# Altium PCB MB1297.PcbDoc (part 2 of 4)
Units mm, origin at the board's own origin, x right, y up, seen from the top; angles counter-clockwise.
Board outline 90.1 x 62.11 mm, 4 copper layers (Top Layer, GND, POWER+GND, Bottom Layer), stack 0.778 mm thick; 235 components, 174 nets, 1727 pads, 1 vias.

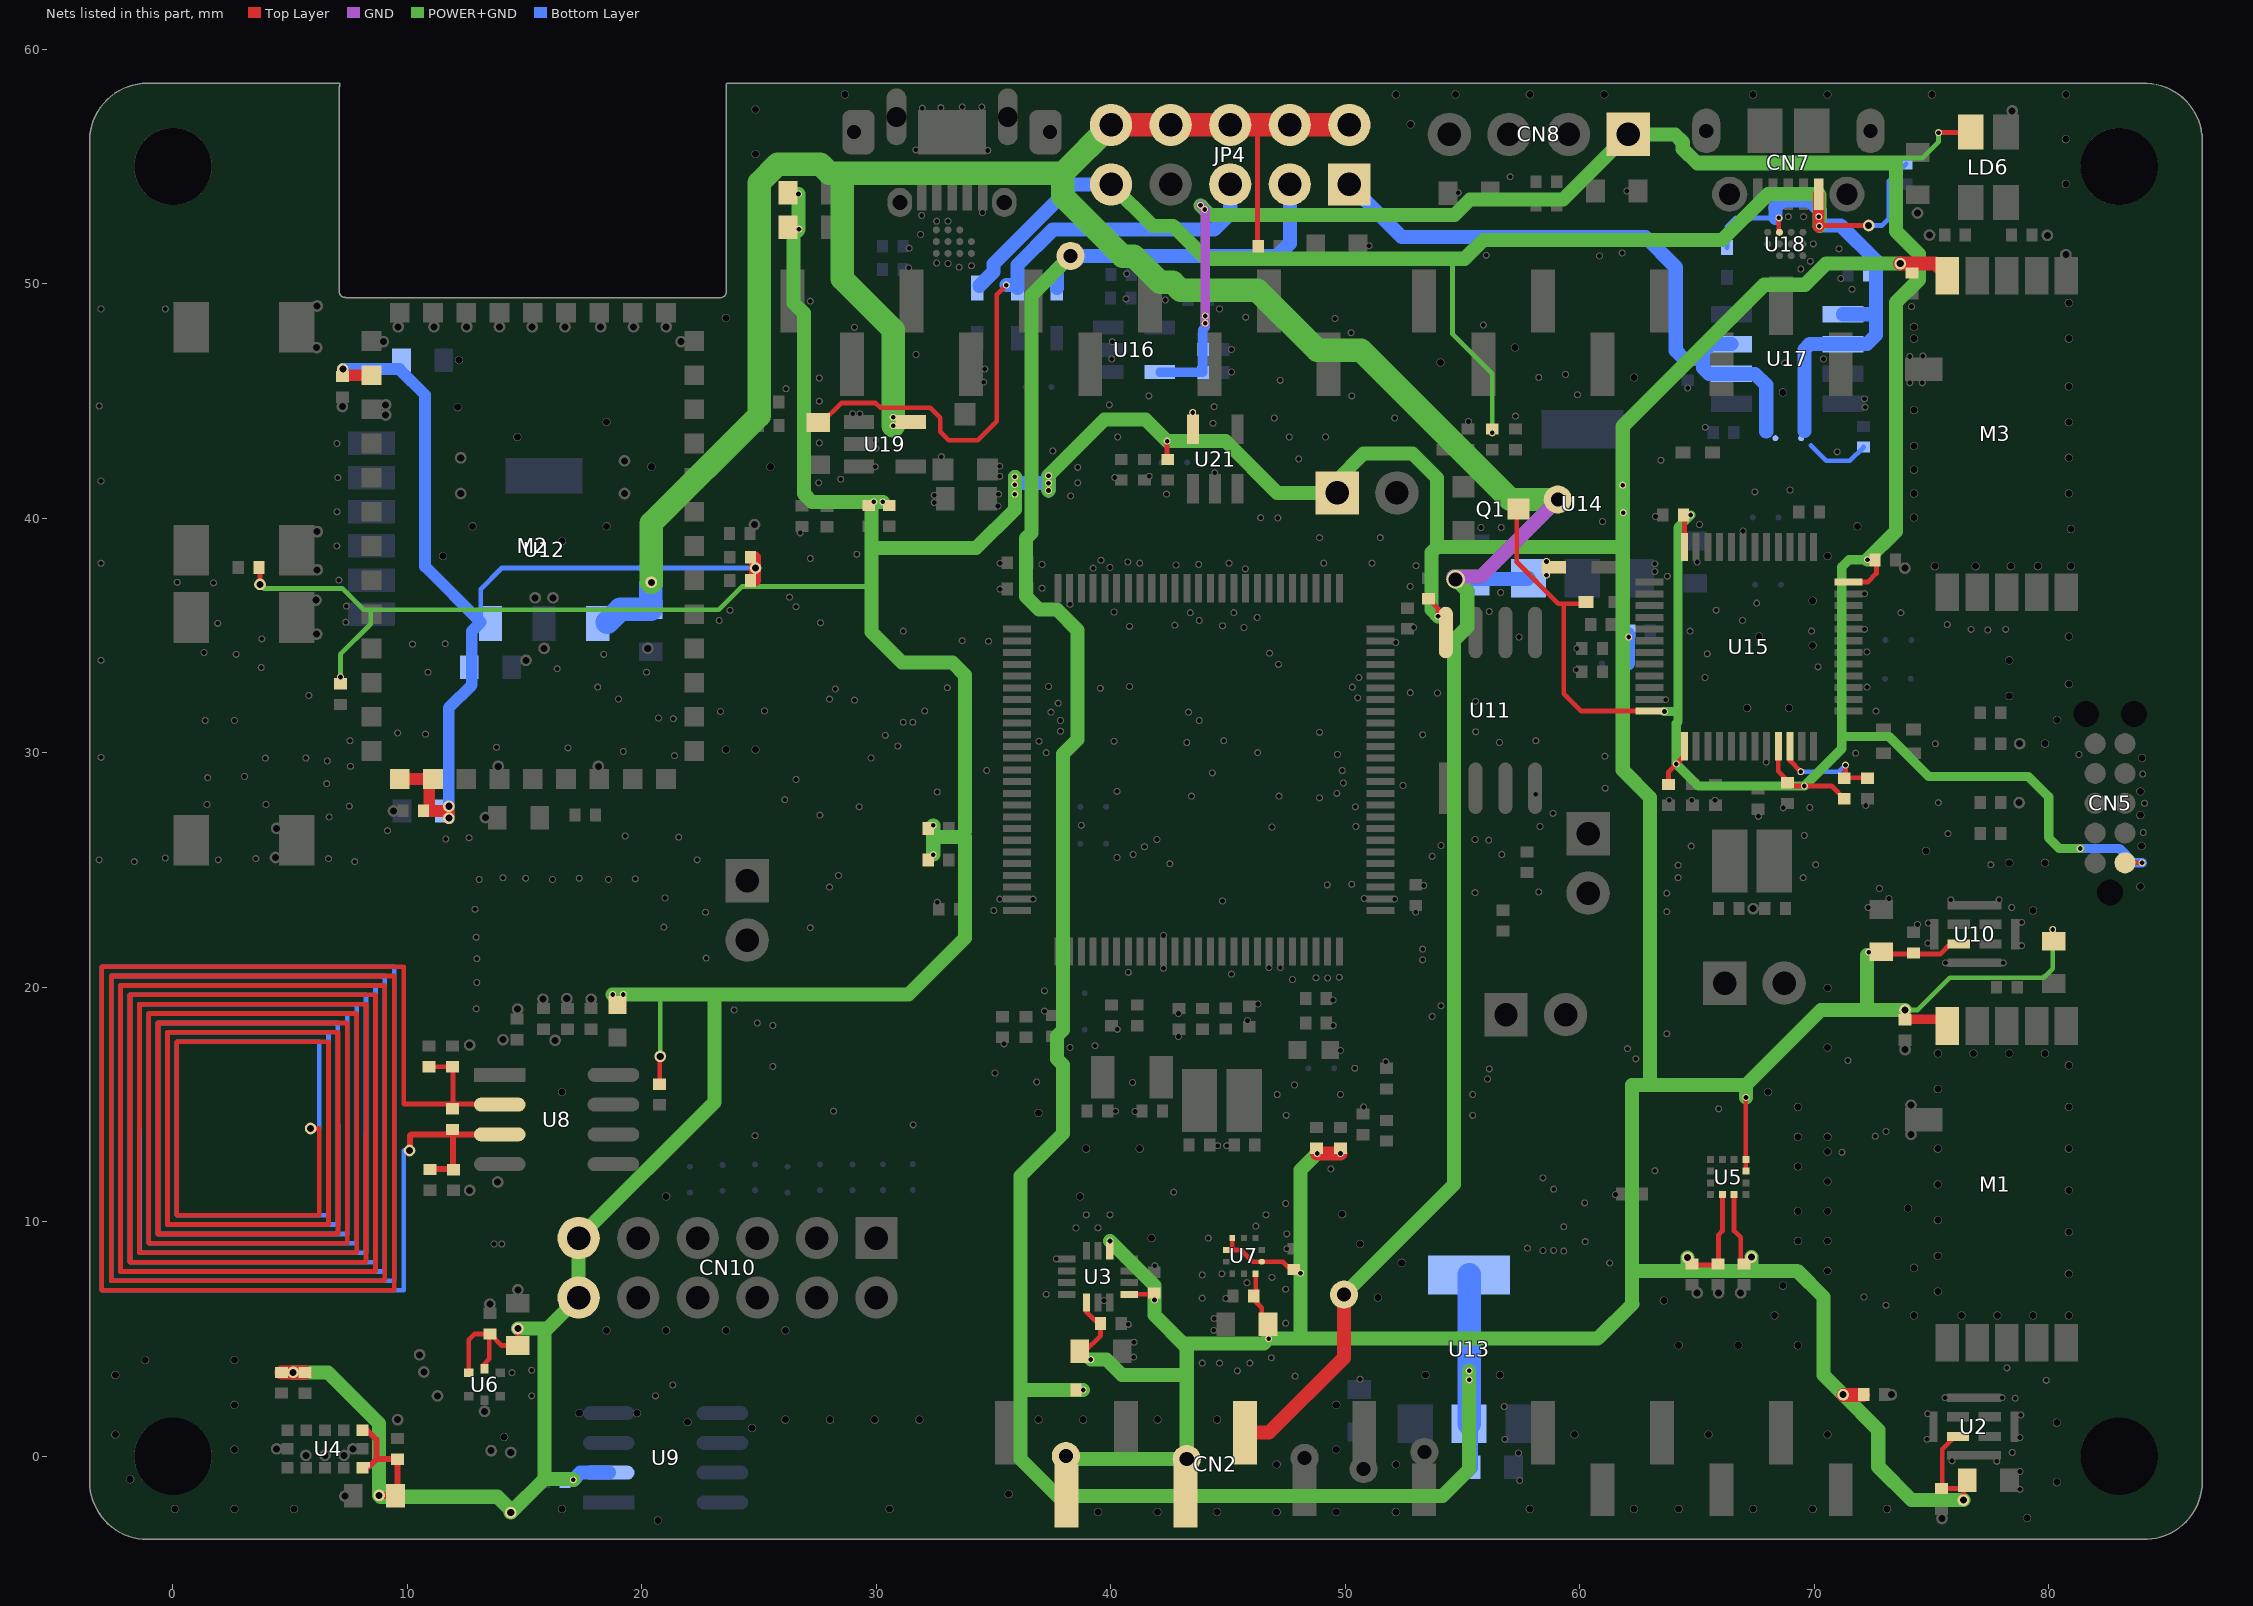
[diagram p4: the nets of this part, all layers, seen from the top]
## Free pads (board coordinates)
  round 0.3 hole 0.2 mask+0.05: 0(-3.068,48.925) 0(17.074,-1.011) 0(24.825,13.666) 0(31.928,52.913) 0(84.003,29.088) 1(-0.325,48.925) 1(6.992,43.187) 1(31.565,14.127) 1(32.568,52.667) 1(84.028,26.599) 2(-3.144,25.43) 2(7.034,41.73) 2(21.316,3.036) 2(28.174,14.711) 2(32.568,50.881) 2(83.978,25.303) 3(-0.325,25.506) 3(6.999,40.273) 3(20.579,2.57) 3(64.115,29.52) 4(-1.646,25.354) 4(6.99,38.816) 4(33.533,50.703) 4(69.576,28.58) 5(-3.068,29.799) 5(7.076,37.359) 5(34.055,50.766) 5(63.658,32.263) 6(-3.068,33.939) 6(7.397,36.251) 6(33.051,52.667) 6(72.141,36.784) 7(-3.068,38.079) 7(7.371,35.565) 7(33.055,50.86) 7(72.141,35.26) 8(-3.068,41.585) 8(31.882,52.1) 8(46.767,34.244) 8(67.95,29.596) 9(-3.144,44.785) 9(39.578,38.206) 9(47.148,33.766) 9(72.268,38.232) 10(1.732,37.241) 10(39.959,37.902) 10(65.004,38.13) 11(0.183,37.267) 11(47.452,10.774) 11(63.225,40.075) 11(68.89,52.862) 12(1.91,35.514) 12(46.614,10.292) 12(64.724,40.137) 12(69.54,52.862) 13(1.478,28.935) 13(39.959,10.292) 13(66.96,39.451) 13(69.423,50.627) 14(3.053,28.986) 14(38.951,10.292) 14(68.964,41.201) 14(69.83,50.957) 15(1.377,31.374) 15(15.296,2.57) 15(59.873,34.447) 15(69.957,51.7) 16(2.621,31.374) 16(15.296,3.662) 16(59.848,33.533) 16(68.488,52.807) 17(1.326,34.269) 17(39.451,9.737) 17(70.19,52.862) 18(2.698,34.193) 18(38.512,9.733) 18(67.464,41.123) 18(70.215,52.456) 19(6.558,28.681) 19(35.54,49.941) 19(47.095,15.423) 19(74.148,49.027) 20(7.524,27.716) 20(29.291,44.455) 20(47.478,14.534) 20(70.973,42.829) 21(1.936,25.43) 21(32.466,40.975) 21(48.799,12.908) 21(76.688,35.26) 22(3.536,25.481) 22(32.466,40.67) 22(49.789,12.908) 22(77.399,35.235) 23(1.453,27.792) 23(37.242,6.9) 23(47.222,45.879) 23(78.161,35.26) 24(3.968,27.792) 24(46.238,35.768) 24(47.605,43.464) 25(6.66,27.259) 25(43.769,35.641) 25(48.011,42.524) 25(72.598,13.645) 26(6.635,25.481) 26(43.388,35.971) 27(7.752,25.354) 27(31.691,46.982) 27(37.445,31.729) 27(73.056,13.848) 28(13.061,24.592) 28(31.374,50.678) 28(37.851,31.374) 28(61.083,28.48) 29(12.934,19.08) 29(31.4,51.516) 29(43.769,31.374) 29(64.191,25.202) 30(12.959,20.198) 30(43.312,31.729) 30(47.744,20.325) 31(12.959,21.214) 31(46.259,30.002) 31(46.868,26.827) 31(77.526,25.227) 32(12.934,22.128) 32(37.242,30.002) 32(40.95,25.659) 32(70.058,25.227) 33(12.883,23.322) 33(18.75,19.69) 33(33.66,34.777) 33(58.298,26.853) 34(14.077,24.668) 34(19.208,19.69) 34(63.708,24.008) 35(15.042,24.643) 35(37.851,30.917) 35(45.395,3.637) 35(69.804,27.665) 36(16.185,24.592) 36(44.76,35.412) 36(46.271,19.283) 36(64.191,24.668) 37(17.328,24.643) 37(44.735,7.777) 37(44.811,30.51) 37(69.525,24.668) 38(18.573,24.592) 38(37.525,42.868) 38(45.801,7.396) 38(69.576,26.472) 39(19.716,24.617) 39(44.158,9.293) 39(64.75,26.014) 40(20.935,22.56) 40(45.674,35.336) 40(58.857,27.411) 41(20.986,23.805) 41(46.182,9.809) 41(63.607,31.755) 42(9.149,26.675) 42(48.087,7.803) 42(63.708,18.013) 43(11.638,26.319) 43(44.9,6.725) 43(47.833,15.829) 43(61.067,29.85) 43(62.032,17.378) 44(12.629,26.37) 44(44.404,5.872) 44(50.399,16.54) 44(62.388,16.947) 45(19.284,26.446) 45(44.392,5.364) 45(50.78,14.889) 45(65.817,36.073) 45(84.079,27.843) 46(21.57,26.395) 46(46.729,5.009) 46(51.725,16.825) 46(63.708,23.22) 46(81.285,29.926) 47(22.357,25.43) 47(37.165,19.842) 47(38.816,2.824) 47(55.53,24.033) 48(22.713,23.195) 48(39.147,4.12) 48(40.747,20.63) 49(22.738,21.239) 49(58.247,24.059) 50(23.932,19.029) 50(38.258,17.429) 50(40.988,4.856) 50(48.9,39.172) 50(67.544,36.378) 51(13.797,30.231) 51(39.324,17.505) 51(40.975,4.221) 51(49.078,38.079) 52(16.845,30.205) 52(40.747,5.618) 52(42.88,18.877) 52(56.114,26.268) 53(19.208,30.053) 53(40.264,25.532) 53(41.864,6.66) 53(56.673,25.659) 53(61.829,41.407) 54(21.392,29.875) 54(38.74,26.903) 54(41.875,8.125) 54(55.53,26.294) 54(61.854,40.238) 55(20.706,31.475) 55(39.705,6.634) 55(40.264,28.351) 55(56.622,36.835) 56(14.458,3.561) 56(21.341,31.45) 56(39.959,9.174) 57(14.026,9.047) 57(23.348,31.755) 57(27.183,22.535) 57(37.673,8.412) 57(55.885,48.239) 58(13.696,9.047) 58(24.923,18.471) 58(25.227,31.78) 58(50.272,45.217) 58(53.929,32.542) 59(20.198,33.431) 59(25.583,18.369) 59(51.008,51.618) 59(53.294,30.764) 59(74.072,46.893) 60(16.388,33.584) 60(25.583,16.616) 60(52.768,32.561) 60(74.63,46.919) 61(18.369,34.193) 61(50.805,23.779) 61(56.571,30.434) 61(74.072,45.776) 62(10.876,33.431) 62(52.101,23.754) 62(55.555,30.891) 62(74.605,45.776) 63(11.613,34.65) 63(42.322,49.306) 63(53,23.2) 63(55.553,32.188) 63(64.6,45.55) 64(10.216,34.625) 64(40.671,50.424) 64(53.345,24.338) 64(58.12,30.51) 64(65.35,43.875) 65(3.942,29.768) 65(40.645,49.357) 65(44.328,29.139) 65(58.12,28.224) 65(72.141,45.09) 66(5.669,29.774) 66(45.141,47.198) 66(47.224,20.833) 66(56.139,36.022) 66(72.167,44.734) 67(5.796,32.441) 67(45.141,46.233) 67(53.955,35.819) 67(68.738,46.614) 68(3.764,33.634) 68(52.913,35.336) 68(59.39,46.131) 69(3.79,34.854) 69(46.741,20.833) 69(52.151,34.701) 69(56.012,51.211) 69(70.389,46.792) 70(6.584,29.647) 70(48.748,20.401) 70(56.8,0.716) 70(60.838,51.186) 70(72.243,34.295) 71(7.574,29.418) 71(49.244,20.389) 71(56.774,2.113) 71(63.734,37.523) 71(72.243,32.796) 72(7.549,30.51) 72(49.744,20.421) 72(57.384,0.132) 72(75.299,56.444) 72(75.697,26.548) 73(9.581,30.84) 73(41.433,25.989) 73(57.435,-1.037) 73(81.336,25.913) 74(10.775,30.79) 74(56.647,39.603) 74(71.049,51.491) 74(75.291,27.869) 75(39.553,32.745) 75(49.561,48.519) 75(55.784,39.603) 75(59.314,9.784) 75(75.164,30.383) 76(37.343,32.822) 76(37.343,41.178) 76(51.135,38.079) 76(59.314,8.742) 76(72.294,23.398) 77(37.343,41.813) 77(57.028,54.564) 77(58.426,8.768) 77(73.183,23.779) 78(37.343,41.496) 78(58.882,8.768) 78(74.4,22.675) 79(35.905,41.762) 79(60.229,9.149) 79(72.319,21.493) 80(35.895,41.432) 80(60.203,10.8) 80(74.859,22.738) 81(35.905,41.026) 81(50.246,47.909) 81(58.426,11.866) 81(74.84,21.874) 82(31.958,57.485) 82(58.882,11.384) 82(75.824,23.728) 83(7.143,33.228) 83(32.746,57.51) 83(41.966,26.295) 83(77.882,23.728) 84(34.498,57.536) 84(42.512,25.266) 84(78.84,22.763) 85(34.752,55.682) 85(49.23,24.363) 85(61.803,51.313) 85(78.84,21.773) 86(31.679,55.707) 86(50.272,24.389) 86(63.456,42.469) 86(75.596,21.036) 87(33.66,57.536) 87(53.701,25.583) 87(78.059,21.036) 88(34.524,53.04) 88(54.082,26.04) 88(80.168,22.458) 89(34.625,46.36) 89(53.701,18.75) 89(75.57,2.494) 90(34.575,45.801) 90(54.082,19.207) 90(78.009,2.494) 91(53.294,21.62) 91(63.2,12.171) 91(78.807,1.757) 92(53.294,21.163) 92(65.918,14.813) 92(78.771,0.792) 93(35.438,17.582) 93(37.75,32.11) 94(37.165,18.979) 94(78.44,0.157) 95(34.778,34.752) 95(40.925,15.931) 95(74.834,1.808) 96(74.808,0.716) 97(36.833,15.956) 97(38.258,36.327) 97(75.875,-0.198) 98(77.78,-0.224) 99(39.244,37.872) 99(78.771,-0.656) 100(78.771,-1.418) 101(26.294,36.632) 101(50.627,3.281) 102(26.574,36.225) 102(71.76,29.977) 103(26.574,28.859) 103(72.631,31.773) 104(26.091,27.996) 104(71.328,29.469) 105(47.452,7.117) 105(69.423,29.189) 106(27.59,27.335) 106(47.452,5.669) 106(72.2,27.75) 107(27.615,35.539) 107(46.868,7.625) 107(67.62,27.284) 108(29.266,27.691) 108(43.896,7.726) 108(68.675,27.65) 109(32.593,28.326) 109(43.896,6.736) 109(65.766,27.97) 110(29.063,48.138) 110(43.896,3.967) 110(64.775,27.97) 111(27.183,49.255) 111(44.633,3.967) 111(63.81,27.97) 112(29.888,40.696) 112(42.245,22.204) 112(45.928,3.967) 113(30.275,40.696) 113(42.245,20.807) 113(46.843,4.196) 114(26.75,39.375) 114(47.859,3.408) 115(27.183,38.283) 115(45.141,20.553) 115(49.475,19.45) 116(30.714,44.302) 116(44.76,23.678) 116(49.484,18.369) 117(30.714,43.947) 117(47.173,28.148) 117(49.789,17.302) 118(29.952,43.337) 118(43.439,28.148) 119(29.977,42.982) 119(43.236,30.434) 119(45.825,18.575) 120(42.779,38.003) 120(42.88,17.9) 121(29.952,42.194) 121(40.275,18.2) 121(43.744,38.029) 122(35.26,41.788) 122(44.557,13.238) 122(47.122,40.01) 123(35.26,42.22) 123(38.588,42.169) 123(44.938,13.238) 124(35.21,41.026) 124(38.588,41.508) 124(40.2,14.711) 125(35.184,40.518) 125(39.934,44.836) 125(41.025,14.7) 126(28.987,44.455) 126(44.354,44.048) 126(54.818,53.878) 127(35.275,38.075) 127(44.404,44.76) 127(62.007,53.954) 128(26.675,53.827) 128(35.275,36.975) 128(45.751,48.57) 129(26.701,52.329) 129(27.564,45.979) 129(37.064,38.029) 130(27.564,44.988) 130(31.552,31.298) 130(37.064,37.016) 131(27.564,43.21) 131(30.384,30.739) 131(46.386,40.022) 132(27.539,41.508) 132(30.917,30.282) 132(45.735,37.841) 133(29.164,38.46) 133(29.774,29.774) 133(50.424,27.691) 134(29.063,32.237) 134(50.45,26.853) 135(35.006,23.271) 135(49.916,28.707) 136(35.26,23.754) 136(49.865,29.24) 137(36.683,23.754) 137(50.577,33.203) 138(50.297,32.796) 139(50.526,32.339) 140(32.425,25.65) 140(49.637,28.266) 141(32.425,26.9) 141(49.662,29.926) 142(32.6,23.625) 143(32.06,31.78) 143(52.761,37.089) 144(26.142,45.522) 144(33.025,32.771) 145(28.381,24.766) 145(28.479,41.661) 146(28,24.266) 146(32.771,42.626) 147(28.25,32.72) 148(28,32.284) 149(23.297,35.641) 149(61.524,11.155) 150(23.754,36.073) 150(67.087,15.296) 151(55.428,14.534) 152(31.146,31.298) 152(55.428,15.423) 153(18.115,32.796) 153(49.789,15.423) 154(19.004,32.288) 155(31.146,35.184) 155(42.728,35.438) 156(34.702,29.24) 156(42.677,11.257) 157(57.765,8.869) 159(61.27,8.234) 160(75.672,35.463) 161(73.056,6.431) 162(79.888,3.231) 163(78.212,3.764) 164(72.116,6.787) 165(78.567,2.469) 166(78.415,23.398) 167(71.176,12.959) 168(72.776,24.211) 169(71.43,16.87) 171(41.619,45.217) 172(41.636,41.788) 173(42.372,41.026) 174(43.49,44.506) 175(44.43,41.94) 177(42.398,43.286) 179(41.229,38.079) 180(40.721,38.13) 181(40.29,43.464)
  round 3.3 hole 3.3 unplated mask+0.05: 0(0,0) 0(0,55) 0(83,0) 0(83,55)
  round 0.5 hole 0.3 mask+0.05: 0(10.089,13.035) 0(13.569,0.233) 0(72.319,52.481) 1(5.873,13.973) 1(14.407,0.157) 1(74.402,53.015) 2(13.518,6.482) 2(14.712,7.091) 3(13.328,27.234) 4(11.765,27.716) 4(14.407,-2.408) 5(7.333,-1.71) 5(11.765,27.208) 6(8.794,-1.672) 6(15.829,34.447) 7(7.673,0.31) 7(15.448,36.606) 8(7.295,0.03) 8(16.21,36.606) 9(6.482,0.03) 9(12.273,42.575) 10(5.669,0.03) 10(12.273,41.051) 11(4.425,0.31) 11(19.258,42.448) 12(9.581,1.554) 12(19.258,41.051) 13(5.125,3.575) 14(11.283,2.57) 15(13.289,1.91) 15(20.401,37.267) 16(8.971,47.528) 16(14.712,5.44) 17(9.606,48.163) 17(10.699,3.586) 18(10.521,4.323) 18(11.13,48.163) 19(12.527,48.163) 20(13.924,48.163) 21(15.321,48.163) 22(16.718,48.163) 23(18.242,48.163) 24(12.654,17.531) 24(19.639,48.163) 25(12.654,11.333) 25(21.036,48.163) 26(13.848,11.689) 26(21.671,47.528) 27(14.7,19.064) 27(24.846,37.876) 28(15.779,19.487) 28(24.8,39.725) 29(16.795,19.512) 30(17.836,19.487) 31(16.299,17.734) 32(14.077,17.759) 33(20.782,17.048) 37(76.358,-1.875) 39(75.443,-2.662) 44(71.227,2.621) 45(73.284,2.621) 50(78.758,30.383) 51(78.733,27.869) 54(73.868,19.029) 56(74.122,14.965) 57(74.122,13.721) 58(73.875,17.337) 68(67.315,8.488) 69(64.597,8.463) 70(65.004,6.964) 71(65.918,6.964) 72(66.858,6.964) 81(73.863,37.869) 82(67.391,23.347) 83(7.244,46.36) 84(7.225,44.762) 85(9.073,44.836) 86(9.073,44.404) 87(3.714,37.178) 88(15.055,33.939) 89(20.249,34.447) 91(9.403,27.513) 92(13.874,29.418) 93(18.141,29.418) 94(4.425,26.776) 95(4.374,25.532) 96(6.101,36.505) 97(6.127,35.057) 98(6.152,39.426) 99(6.152,37.8) 100(6.152,49.052) 101(6.127,47.274) 107(78.44,57.37) 108(80.726,51.237) 109(73.665,50.856) 110(74.91,52.075) 111(79.939,52.062)
  round 1.2 hole 0.6 mask+0.05: 48(38.079,0.004) 48(38.283,51.186) 48(43.235,-0.123) 48(48.264,-0.072) 48(49.942,6.888) 48(50.779,-0.555) 48(53.371,0.183) 48(59.06,40.797)
  round 0.8 hole 0.6 mask+0.05: 48(54.702,37.394)
  round 0.3 hole 0.2 mask-0.01: 182(55.28,3.637) 183(55.28,3.256) 184(40.798,35.387) 186(48.9,28.072) 187(48.9,30.866) 191(40.137,35.997) 192(40.137,30.485) 193(40.798,32.822) 194(36.937,30.485) 195(56.139,16.515) 196(49.383,12.248) 197(35.057,16.337) 198(45.244,35.973) 199(56.063,16.083) 202(45.039,38.079) 203(46.97,44.277) 204(52.101,44.277) 205(58.578,37.571) 206(58.578,38.156) 207(56.266,43.642) 208(43.82,53.345) 209(43.998,53.167) 210(44.023,48.62) 211(44.023,48.316) 212(38.283,40.95) 213(49.154,43.464) 215(60.965,39.857) 216(66.934,35.641) 217(65.105,39.73) 218(63.2,38.054) 219(63.2,37.724) 221(62.083,34.93) 222(64.699,35.184) 223(59.898,45.268) 224(58.247,46.004) 225(55.25,44.125) 226(57.257,44.353) 228(57.409,34.93) 229(52.458,28.604) 230(53.015,37.978) 231(44.633,48.925) 232(40.061,47.528) 233(40.036,46.792) 234(47.503,9.479) 235(47.503,8.844) 236(40.163,41.737) 237(71.125,50.225) 238(71.608,49.763) 239(65.334,33.203) 241(70.16,33.66) 244(51.491,39.172) 245(73.691,35.971) 246(69.881,35.184) 247(65.436,34.219)
  round 0.35 hole 0.3 mask-0.01: 249(80.853,45.623) 250(80.853,47.655) 251(80.853,49.179) 252(80.853,44.099) 253(80.853,42.575) 254(80.853,41.051) 255(80.94,39.538) 256(80.94,37.952) 257(79.533,37.952) 258(78.379,37.952) 259(76.881,37.952) 260(75.138,37.952) 261(74.249,40.035) 262(74.249,41.051) 263(74.249,42.067) 264(74.249,43.083) 265(74.249,44.607) 266(74.249,47.655) 267(74.249,48.163) 268(80.853,34.955) 269(80.853,32.923) 270(78.313,33.939) 271(78.313,32.415) 272(80.345,31.399) 273(79.837,30.383) 274(79.837,25.303) 275(78.313,25.303) 276(74.757,25.811) 277(79.329,23.271) 278(83.901,24.287) 279(83.901,27.335) 280(83.901,28.351) 281(83.978,29.774) 282(83.952,26.014) 283(80.853,16.667) 284(80.853,14.889) 285(80.853,13.111) 286(80.853,11.333) 287(80.853,9.555) 288(80.853,5.999) 289(80.853,7.777) 290(75.265,17.175) 291(75.265,15.651) 292(75.265,13.111) 293(75.265,11.587) 294(75.265,10.063) 295(75.265,8.539) 296(75.265,7.015) 297(76.281,5.999) 298(77.805,5.999) 299(79.329,5.999) 300(76.789,17.175) 301(78.313,17.175) 302(79.837,17.175) 303(73.995,10.571) 304(74.249,8.031) 305(74.249,5.999) 306(70.566,7.904) 307(70.566,9.174) 308(70.566,10.444) 309(70.566,11.714) 310(70.566,12.984) 311(68.026,15.524) 312(69.296,14.889) 313(70.566,13.619) 314(69.296,13.619) 315(69.296,12.349) 316(69.296,10.444) 317(69.296,9.174) 318(68.661,7.269) 319(68.306,5.999) 320(69.296,4.729) 321(70.566,17.429) 322(70.566,19.969) 327(24.846,57.434) 328(28.656,58.069) 329(24.846,55.529) 330(80.726,58.069) 331(75.011,58.069) 332(80.726,56.164) 333(80.726,54.259) 334(52.151,58.069) 335(52.786,56.799) 336(54.691,58.069) 337(57.866,58.069) 338(61.041,58.069) 339(67.391,58.069) 340(70.566,58.069) 341(57.231,47.274) 342(54.056,46.639) 343(62.311,46.004) 344(68.661,45.369) 345(71.836,39.654) 346(70.566,38.384) 347(69.931,36.479) 348(69.931,34.574) 349(65.486,0.919) 350(67.391,-2.256) 351(69.931,-2.256) 352(64.216,-2.256) 353(62.311,-2.256) 354(57.866,-2.256) 355(52.151,-2.383) 356(49.611,-2.383) 357(47.071,-2.383) 358(44.531,-2.383) 359(41.991,-2.383) 360(39.451,-2.383) 361(59.771,0.919) 362(49.611,0.284) 363(47.071,-0.351) 364(52.151,-0.351) 365(53.421,3.459) 366(56.596,3.459) 367(64.216,4.729) 368(66.756,4.729) 369(63.581,6.634) 370(70.566,0.919) 371(73.106,-2.256) 372(41.991,1.554) 373(44.531,1.554) 374(38.816,1.554) 375(36.911,1.554) 376(49.611,2.189) 377(35.641,-1.621) 378(31.831,1.554) 379(30.561,-2.256) 380(20.681,-2.738) 381(16.591,-2.256) 382(14.128,0.818) 383(5.161,-2.256) 384(2.621,-2.256) 385(0.081,-2.256) 386(-1.824,-0.986) 387(-2.459,0.919) 388(-2.459,3.459) 389(-1.189,4.094) 390(2.621,4.094) 391(2.621,2.189) 392(2.621,0.284) 393(17.328,1.834) 394(19.792,1.834) 395(21.951,1.453) 396(24.694,1.199) 397(26.116,1.554) 398(28.021,1.554) 399(29.926,1.554) 400(18.496,5.364) 401(21.036,5.364) 402(23.576,5.364) 403(26.116,5.364) 404(16.591,15.524) 405(21.036,11.079) 406(12.146,44.734) 407(14.686,43.464) 408(18.496,44.099) 409(25.481,42.194) 410(20.401,42.194) 411(11.511,38.384) 412(12.781,39.654) 413(16.591,39.019) 414(18.496,39.654) 415(24.846,30.129) 416(23.576,30.129) 417(12.197,46.741) 418(23.576,48.544) 420(36.911,14.635) 421(41.737,9.301) 422(41.229,13.111) 423(38.943,13.111) 424(38.689,11.079) 425(49.865,10.317) 426(50.627,9.047) 427(52.405,8.245) 428(51.389,6.761) 429(80.345,1.427) 430(80.345,-1.113) 431(79.075,-2.637) 432(67.137,31.907) 433(68.915,31.907) 434(67.645,34.955)

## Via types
v1: diameter 0.4, hole 0.2, Top Layer to Bottom Layer, tented both sides, 1 vias

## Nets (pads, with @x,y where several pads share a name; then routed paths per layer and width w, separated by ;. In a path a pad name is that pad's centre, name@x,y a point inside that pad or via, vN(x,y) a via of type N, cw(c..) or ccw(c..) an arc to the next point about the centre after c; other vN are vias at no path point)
3V3: C16.1 C17.2 C18.1 C19.1 C20.1 C21.1 C22.1 C24.1 C25.1 C26.1 C27.1 C28.1 C29.1 C30.1 C31.1 C33.1 C42.1 C43.1 C45.1 C46.1 C48.1 C73.1 C74.1 CN2.2 CN2.4 CN10.6 CN10.12 JP5.1 L2.2 LD4.A LD8.A LD9.A M1.5 M3.5 pad.0@17.074,-1.011 pad.4@14.407,-2.408 pad.6@8.794,-1.672 pad.13@5.125,3.575 pad.16@14.712,5.44 pad.21@48.799,12.908 pad.22@49.789,12.908 pad.33@18.75,19.69 pad.33@20.782,17.048 pad.34@19.208,19.69 pad.37@76.358,-1.875 pad.42@48.087,7.803 pad.44@71.227,2.621 pad.46@46.729,5.009 pad.48@38.079,0.004 pad.48@39.147,4.12 pad.48@43.235,-0.123 pad.53@41.864,6.66 pad.53@61.829,41.407 pad.54@61.854,40.238 pad.54@73.868,19.029 pad.56@39.959,9.174 pad.67@53.955,35.819 pad.68@67.315,8.488 pad.69@64.597,8.463 pad.76@37.343,41.178 pad.77@37.343,41.813 pad.78@37.343,41.496 pad.79@35.905,41.762 pad.79@72.319,21.493 pad.80@35.895,41.432 pad.81@35.905,41.026 pad.83@7.143,33.228 pad.87@3.714,37.178 pad.88@80.168,22.458 pad.109@73.665,50.856 pad.112@29.888,40.696 pad.113@30.275,40.696 pad.128@26.675,53.827 pad.129@26.701,52.329 pad.140@32.425,25.65 pad.141@32.425,26.9 pad.150@67.087,15.296 pad.174 pad.177 pad.221 R4.1 R8.1 R9.1 R10.1 R11.1 R14.1 R15.1 R23.2 R26.2 R58.1 R62.1 R67.1 SB4.2 U2.1 U3.5 U3.8 U3.12 U4.1 U4.11 U5.5 U5.6 U5.9 U5.10 U6.1 U6.6 U7.1 U7.5 U7.6 U7.10 U9.2 U10.1 U11.8 U21.5 | length 382.9
  Top Layer w0.204: pad.87@3.714,37.178 R23.2@3.714,37.902 ; U6.1@12.614,3.553 12.614,4.964 12.863,5.212 12.865,5.21 C28.1@13.493,5.21 ; U6.6@13.289,3.728 13.289,3.942 13.493,4.145 C28.1@13.493,5.21 ; pad.16@14.712,5.44 C27.1@14.712,4.716 14.019,4.716 C28.1@13.525,5.21 C28.1@13.493,5.21 ; R4.1@20.757,15.865 pad.33@20.757,17.023 ; C18.1@38.677,4.475 38.892,4.475 39.56,5.143 39.56,5.54 38.951,6.149 U3.5@38.951,6.55 ; U3.8@40.781,6.9 41.749,6.9 C20.1@41.864,7.015 ; C73.1@42.398,42.702 pad.177@42.398,43.286 ; U7.6@44.912,8.789 45.162,8.789 ; U7.5@45.174,9.302 45.174,8.801 45.182,8.793 45.547,8.793 46.051,8.289 U7.1@46.437,8.289 47.321,8.289 C31.1@47.706,7.904 ; U7.10@46.174,7.777 46.174,6.591 46.436,6.329 46.436,5.885 C30.1@46.703,5.618 ; C48.1@53.475,36.56 53.54,36.56 53.955,36.145 pad.67@53.955,35.819 ; U11.8@54.285,34.231 U11.8@54.285,35.126 54.285,35.768 U11.8@54.336,35.819 ; C24.1@64.978,8.15 65.918,8.15 65.918,9.446 66.079,9.606 U5.5@66.079,11.154 ; U5.6@66.579,11.154 66.579,9.606 66.858,9.327 66.858,8.332 C26.1@67,8.19 ; U5.9@67.079,12.154 U5.10@67.079,12.654 67.079,15.288 pad.150@67.087,15.296 ; C46.1@72.852,21.506 72.947,21.412 75.375,21.412 75.804,21.841 U10.1@76.165,21.841 ; C43.1@73.894,18.521 C43.1@73.997,18.625 ; M1.5@75.289,18.625 75.57,18.344 M1.5@75.672,18.344 ; C17.2@75.425,-1.385 C17.2@75.453,-1.385 ; U2.1@76.132,0.837 75.993,0.837 75.453,0.296 C17.2@75.453,-1.385 ; pad.37@76.358,-1.875 C16.1@76.358,-1.385 ; C17.2@75.453,-1.385 C16.1@76.358,-1.385 ; C16.1@76.358,-1.385 C16.1@76.358,-1.275 ; C16.1@76.358,-1.275 76.583,-1.275 76.358,-1.049 C16.1@76.358,-1.275
  Top Layer w0.254: U4.11@8.082,1.11 8.273,1.11 8.682,0.7 8.682,-0.13 ; pad.6@8.794,-1.672 C21.1@9.467,-1.672 ; C21.1@9.492,-1.697 9.581,-1.608 C22.1@9.581,-0.13 8.682,-0.13 ; U4.1@8.154,-0.443 8.106,-0.49 U4.1@8.082,-0.49 8.13,-0.443 U4.1@8.154,-0.443 ; U4.1@8.154,-0.443 8.37,-0.443 8.682,-0.13
  Top Layer w0.4: C43.1@73.997,18.625 M1.5@75.289,18.625
  Top Layer w0.6: R15.1@4.628,3.569 4.89,3.569 pad.13@5.125,3.575 5.335,3.565 R14.1@5.625,3.565 ; pad.21@48.799,12.908 pad.22@49.789,12.908 ; pad.44@71.248,2.6 R67.1@72.085,2.6 ; pad.109@73.665,50.856 75.164,50.856 M3.5@75.672,50.348
  POWER+GND w0.204: pad.87@3.714,37.178 3.886,37.005 7.222,37.005 8.129,36.098 8.438,36.098 ; pad.83@7.143,33.228 7.143,34.193 8.438,35.489 8.438,36.098 ; 20.757,19.664 20.782,19.639 pad.33@20.782,17.048 ; 29.791,37.114 29.766,37.089 24.27,37.089 23.279,36.098 8.438,36.098 ; 29.901,38.722 pad.112@29.901,40.645 ; 43.414,43.286 43.49,43.363 pad.174@43.49,44.506 ; pad.54@73.868,19.029 74.402,19.029 75.773,20.401 79.787,20.401 80.168,20.782 pad.88@80.168,22.458
  POWER+GND w0.6: pad.13@5.125,3.575 6.617,3.575 8.794,1.398 pad.6@8.794,-1.672 8.853,-1.731 13.844,-1.731 14.407,-2.294 pad.4@14.407,-2.408 15.848,-0.967 ; pad.16@14.712,5.44 15.982,5.44 ; pad.0@17.074,-1.011 17.03,-0.967 15.848,-0.967 ; pad.33@18.75,19.69 pad.34@19.208,19.69 23.094,19.69 ; pad.128@26.675,53.827 26.675,52.303 26.472,52.1 26.472,49.186 26.904,48.754 26.904,41.046 27.254,40.696 pad.112@29.888,40.696 pad.113@30.275,40.696 ; pad.112@29.888,40.672 29.791,40.576 29.791,37.114 29.791,35.141 31.095,33.838 33.254,33.838 33.787,33.304 33.787,26.65 ; 29.901,38.722 34.252,38.722 35.905,40.375 pad.81@35.905,41.026 pad.79@35.905,41.762 ; pad.140@32.425,25.65 pad.141@32.425,26.9 ; 32.491,26.409 33.787,26.409 33.787,22.103 31.374,19.69 23.094,19.69 ; pad.76@37.343,41.178 pad.78@37.343,41.496 pad.77@37.343,41.813 39.731,44.201 41.483,44.201 pad.177@42.398,43.286 43.414,43.286 44.887,43.286 47.097,41.077 JP5.1@49.658,41.077 49.658,41.631 50.78,42.753 52.863,42.753 53.904,41.712 53.904,38.769 ; pad.48@38.079,0.004 38.206,-0.123 pad.48@43.235,-0.123 43.235,3.459 ; pad.48@39.147,4.12 39.807,4.12 40.467,3.459 43.235,3.459 ; pad.56@39.959,9.174 41.864,7.269 pad.53@41.864,6.66 41.864,6.011 43.235,4.64 ; 48.214,5.009 60.762,5.009 62.248,6.494 ; pad.21@48.799,12.908 48.087,12.197 pad.42@48.087,7.803 48.087,5.009 pad.46@46.729,5.009 46.532,4.812 43.235,4.812 43.235,4.64 ; pad.67@53.955,35.819 53.675,36.098 53.675,38.541 53.904,38.769 ; 62.227,6.515 62.227,15.821 62.997,15.821 ; 62.278,7.904 67.315,7.904 ; 64.597,7.955 pad.69@64.597,8.463 ; pad.150@67.087,15.296 67.079,15.821 ; pad.68@67.315,8.488 67.315,7.904 ; pad.79@72.243,21.366 72.243,19.029 ; pad.109@73.665,50.856 70.509,50.856 69.61,49.957 67.864,49.957 61.829,43.921 pad.53@61.829,41.407 61.829,38.769 ; pad.54@73.868,19.029 72.243,19.029 ; pad.37@76.358,-1.875 74.148,-1.875 72.725,-0.452 72.725,1.122 pad.44@71.227,2.621 70.389,3.459 70.389,6.787 69.271,7.904 67.315,7.904 ; 15.848,-0.967 15.848,5.307 15.982,5.44 ; 15.982,5.44 CN10.12@17.303,6.761 CN10.6@17.303,9.301 23.094,15.092 23.094,19.69 ; 43.235,3.459 43.235,4.64 ; 53.904,38.769 61.829,38.769 ; 61.829,38.769 61.829,29.266 62.997,28.097 62.997,15.821 ; 62.997,15.821 67.079,15.821 ; 67.079,15.821 70.287,19.029 72.243,19.029
  Bottom Layer w0.6: pad.0@17.074,-1.011 17.379,-0.706 U9.2@18.586,-0.706 ; pad.81@35.905,41.026 pad.79@35.905,41.762 ; pad.80@35.968,41.496 pad.78@37.343,41.496 ; pad.76@37.343,41.178 pad.78@37.343,41.496 ; pad.77@37.343,41.813 pad.78@37.343,41.496 ; SB4.2@62.048,33.812 pad.221@62.048,35.066
3V3_ST_LINK: C55.1 C59.1 C60.1 C61.1 C62.1 C63.1 CN5.1 CN8.1 LD6.4 pad.2@83.978,25.303 pad.3@64.115,29.52 pad.4@69.576,28.58 pad.9@72.268,38.232 pad.12@64.724,40.137 pad.41@63.607,31.755 pad.72@75.299,56.444 pad.73@81.336,25.913 pad.208 pad.209 pad.210 pad.211 Q1.3 R30.1 R40.2 U15.1 U15.9 U15.24 U15.36 U15.48 U16.5 | length 140.2
  Top Layer w0.204: Q1.3@57.384,40.391 57.306,40.313 57.306,38.132 59.086,36.352 59.314,36.352 ; R30.1@60.254,36.352 59.314,36.352 ; U15.48@62.964,31.773 60.058,31.773 59.314,32.517 59.314,36.352 ; C60.1@63.785,28.834 63.785,29.189 64.464,29.868 U15.1@64.464,30.273 ; U15.36@64.464,38.773 C63.1@64.464,40.042 ; U15.9@68.464,30.273 68.464,29.211 69.095,28.58 pad.4@69.576,28.58 70.744,28.58 R40.2@71.328,27.996 ; U15.24@71.464,37.273 72.275,37.273 72.649,37.648 C62.1@72.649,38.232 ; pad.72@75.299,56.444 LD6.4@76.701,56.444 ; CN5.1@83.249,25.303 pad.2@83.978,25.303
  GND w0.4: pad.208@43.82,53.345 pad.209@43.998,53.167 44.023,53.142 pad.210@44.023,48.62 pad.211@44.023,48.316
  POWER+GND w0.204: 65.057,55.364 74.617,55.364 75.299,56.046 pad.72@75.299,56.444
  POWER+GND w0.4: pad.41@63.607,31.755 64.186,31.755 ; 64.115,31.247 pad.3@64.115,29.52 65.055,28.58 pad.4@69.576,28.58 71.176,30.18 71.176,30.688 ; 64.186,31.318 64.186,31.755 ; pad.12@64.724,40.137 64.186,39.598 64.186,31.755 ; pad.9@72.268,38.232 71.481,38.232 71.176,37.927 71.176,30.688 ; pad.73@81.336,25.913 80.447,25.913 79.99,26.37 79.99,28.123 79.126,28.986 74.884,28.986 73.183,30.688 71.176,30.688
  POWER+GND w0.6: pad.208@43.82,53.345 pad.209@43.998,53.167 44.233,52.932 54.653,52.932 55.32,53.599 59.289,53.599 CN8.1@62.057,56.367 64.053,56.367 64.388,56.033 64.388,55.753 65.018,55.123 73.475,55.123 73.475,52.24 74.453,51.262 74.453,50.17 73.475,49.192 73.475,39.438 pad.9@72.268,38.232
  Bottom Layer w0.4: U16.5@42.093,46.226 43.925,46.226 43.925,48.039 44.023,48.138 pad.211@44.023,48.316 pad.210@44.023,48.62 ; pad.73@81.336,25.913 83.012,25.913 83.622,25.303 pad.2@83.978,25.303
3V3_WIFI: C44.1 C47.1 C50.1 C75.1 C76.1 M2.2 M2.14 M2.15 pad.4@11.765,27.716 pad.5@11.765,27.208 pad.27@24.846,37.876 pad.83@7.244,46.36 R65.2 R66.2 U12.3 | length 43.1
  Top Layer w0.5: C44.1@7.366,46.101 M2.2@8.467,46.101 ; M2.14@9.667,28.874 M2.15@11.087,28.874 10.925,28.712 10.925,27.513 11.08,27.513 ; 11.087,27.513 11.765,27.513 pad.5@11.765,27.208 ; R66.2@24.821,37.343 R65.2@24.821,38.333
  Bottom Layer w0.204: U12.3@13.129,35.564 13.129,36.98 14.026,37.876 pad.27@24.846,37.876
  Bottom Layer w0.5: pad.83@7.244,46.36 9.657,46.36 10.749,45.268 10.749,37.944 13.129,35.564 12.743,35.177 12.743,32.885 11.765,31.907 pad.4@11.765,27.716 pad.5@11.765,27.208
5V: C40.1 C49.1 CN2.5 D2.1 JP4.2 JP4.4 JP4.6 JP4.8 JP4.10 pad.15@20.401,37.267 pad.48@49.942,6.888 pad.48@54.702,37.394 pad.48@59.06,40.797 pad.116@30.714,44.302 pad.117@30.714,43.947 pad.205 pad.206 R25.1 U12.1 U14.3 U19.5 | length 143.2
  Top Layer w0.204: R25.1@46.259,51.618 46.259,56.723 46.309,56.774
  Top Layer w0.6: CN2.5@45.726,1.001 46.747,1.001 49.942,4.196 pad.48@49.942,6.888
  Top Layer w1: JP4.10@40.01,56.774 JP4.8@42.55,56.774 JP4.6@45.09,56.774 46.309,56.774 JP4.4@47.63,56.774 JP4.2@50.17,56.774
  GND w0.6: pad.48@54.702,37.394 54.61,37.521 55.784,37.521 pad.48@59.06,40.797
  POWER+GND w0.6: pad.48@49.942,6.888 54.634,11.58 54.634,34.796 55.199,35.362 55.199,36.896 pad.48@54.702,37.394 pad.48@54.657,37.439
  POWER+GND w1: pad.15@20.401,37.267 20.401,39.781 24.999,44.379 24.999,54.31 25.786,55.097 27.615,55.097 27.996,54.717 28.542,54.717 ; pad.117@30.714,43.947 pad.116@30.714,44.302 30.714,48.036 28.542,50.208 28.542,54.717 ; JP4.10@40.01,56.774 37.953,54.717 ; pad.48@59.06,40.797 57.028,40.797 50.668,47.157 48.809,47.157 46.253,49.713 42.979,49.713 42.633,50.058 42.1,50.058 40.982,51.176 40.503,51.176 37.953,53.725 37.953,54.717 ; 28.542,54.717 37.953,54.717
  Bottom Layer w0.6: pad.48@54.702,37.394 55.653,37.406 56.384,37.416 56.393,37.406 57.768,37.406 U14.3@57.806,37.444
  Bottom Layer w1: U12.1@18.529,35.564 19.077,36.111 C49.1@20.376,36.111 20.376,37.147 pad.15@20.401,37.172
5V_ARD: C39.1 D3.1 JP4.3 pad.47@38.816,2.824 pad.48@38.283,51.186 pad.182 pad.183 R3.1 U13.2 U13.4 | length 103.6
  POWER+GND w0.6: pad.48@38.283,51.186 36.607,49.509 36.607,39.375 36.378,39.146 36.378,36.657 36.937,36.098 37.706,36.098 38.581,35.223 38.581,30.561 37.96,29.94 37.96,18.166 37.706,17.912 37.706,16.94 37.96,16.686 37.96,13.753 36.149,11.943 36.149,2.748 ; pad.47@38.816,2.824 36.226,2.824 36.149,2.748 ; pad.182@55.28,3.637 pad.183@55.28,3.256 55.28,-0.563 54.145,-1.697 37.724,-1.697 36.149,-0.122 36.149,2.748
  Bottom Layer w0.6: D3.1@37.699,49.817 37.699,50.602 pad.48@38.283,51.186 47.097,51.186 47.63,51.719 JP4.3@47.63,54.234 ; C39.1@55.365,-0.478 U13.2@55.365,1.292
  Bottom Layer w1: U13.2@55.28,1.376 pad.183@55.28,3.256 pad.182@55.28,3.637 U13.4@55.28,7.726
5V_ST_LINK: C65.1 JP4.1 SB11.1 U17.6 U17.7 | length 27.3
  Bottom Layer w0.6: JP4.1@50.17,54.234 52.405,51.999 62.794,51.999 64.089,50.703 64.089,47.147 64.445,46.792 65.258,46.792 ; U17.7@66.464,47.427 65.588,47.427 65.258,47.096 65.258,46.792 ; 67.95,43.693 67.95,45.674 67.468,46.157 U17.6@66.464,46.157 65.512,46.157 65.258,46.411 65.258,46.792
5V_USB_CHARGER: C64.1 CN7.1 D4.1 JP4.9 pad.0@72.319,52.481 pad.16@68.488,52.807 pad.17@70.19,52.862 pad.18@70.215,52.456 pad.207 R48.1 R49.2 R51.2 R52.2 SB11.2 U17.1 U17.2 U18.B3 | length 80.9
  Top Layer w0.204: U18.B3@68.488,52.194 pad.16@68.488,52.807 ; pad.18@70.19,52.43 pad.18@70.215,52.456 70.241,52.481 pad.0@72.319,52.481
  Top Layer w0.5: pad.18@70.19,52.43 pad.17@70.19,52.862 CN7.1@70.19,53.818
  POWER+GND w0.204: 54.564,51.066 54.564,47.858 56.266,46.157 pad.207@56.266,43.642
  POWER+GND w0.6: JP4.9@40.01,54.234 41.788,52.456 42.659,52.456 44.049,51.066 54.564,51.066 55.086,51.066 55.885,51.865 66.066,51.865 68.019,53.818 70.19,53.818 70.215,53.792 pad.18@70.215,52.456
  Bottom Layer w0.204: R49.2@66.274,51.541 66.274,52.432 66.649,52.807 pad.16@68.338,52.807 ; 69.855,43.109 70.516,42.448 71.513,42.448 R51.2@72.1,43.035 ; pad.0@72.319,52.481 72.878,52.481 73.19,52.793 73.19,54.389 R52.2@73.919,55.118
  Bottom Layer w0.6: D4.1@34.399,49.913 34.996,50.51 34.996,50.845 38.385,54.234 JP4.9@40.01,54.234 ; pad.16@68.338,52.807 68.338,53.25 68.636,53.548 69.804,53.548 70.241,53.112 70.241,52.481 71.125,52.481 72.624,50.983 72.624,47.808 72.243,47.427 U17.2@71.214,47.427 69.804,47.427 69.576,47.198 69.576,43.718 ; U17.1@71.214,48.697 72.522,48.697
5V_USB_FS: D5.1 JP4.5 pad.19@35.54,49.941 R61.1 | length 28
  Top Layer w0.204: R61.1@27.513,44.086 27.679,44.086 28.504,44.912 29.977,44.912 30.18,44.709 32.289,44.709 32.72,44.277 32.72,43.693 33.088,43.325 34.321,43.325 35.133,44.138 35.133,49.535 pad.19@35.54,49.941
  Bottom Layer w0.6: pad.19@35.54,49.941 35.892,49.941 D5.1@36.017,49.816 36.017,50.799 37.521,52.303 44.404,52.303 45.09,52.989 JP4.5@45.09,54.234
AIN_1: pad.104@71.328,29.469 pad.105@69.423,29.189 R40.1 R41.1 U15.10 | length 4.8
  Top Layer w0.204: U15.10@68.964,30.273 68.964,29.649 pad.105@69.423,29.189 ; pad.104@71.328,29.469 71.328,28.935 72.243,28.935 R41.1@72.268,28.961
  Bottom Layer w0.204: pad.105@69.423,29.189 71.049,29.189 pad.104@71.328,29.469
ANT: C53.1 C69.1 C70.1 C70.2 C71.1 C72.1 pad.0@10.089,13.035 pad.1@5.873,13.973 U8.2 U8.3 | length 735.2
  Top Layer w0.2: pad.1@5.873,13.975 6.238,13.975 6.236,10.275 0.166,10.275 0.166,17.675 6.638,17.675 6.636,9.875 -0.234,9.875 -0.234,18.075 7.038,18.075 7.036,9.475 -0.634,9.475 -0.634,18.475 7.438,18.475 7.436,9.075 -1.034,9.075 -1.034,18.875 7.838,18.875 7.836,8.675 -1.434,8.675 -1.428,19.272 8.238,19.275 8.236,8.275 -1.834,8.275 -1.834,19.675 8.638,19.675 8.636,7.875 -2.234,7.875 -2.234,20.075 9.038,20.075 9.036,7.475 -2.634,7.475 -2.634,20.475 9.438,20.475 9.436,7.075 -3.034,7.075 -3.034,20.875 9.838,20.875 9.838,15.016 U8.2@13.975,15.016 ; C69.1@10.978,16.6 11.943,16.6 C70.2@11.943,15.042
  Top Layer w0.254: pad.0@10.089,13.035 10.114,13.06 10.114,13.67 10.165,13.721 C70.1@11.943,13.721 ; C72.1@10.969,12.25 11.943,12.25 C70.1@11.943,13.721 ; C70.1@11.943,13.772 C70.1@11.943,13.721 ; U8.3@13.938,13.721 C70.1@11.943,13.721
  Bottom Layer w0.2: pad.1@5.873,13.973 6.235,13.973 ; 6.237,13.975 6.235,17.675 0.165,17.675 0.165,10.275 6.637,10.275 6.635,18.075 -0.235,18.075 -0.235,9.875 7.037,9.875 7.035,18.475 -0.635,18.475 -0.635,9.475 7.437,9.475 7.435,18.875 -1.035,18.875 -1.035,9.075 7.837,9.075 7.835,19.275 -1.435,19.275 -1.429,8.678 8.237,8.675 8.235,19.675 -1.835,19.675 -1.835,8.275 8.637,8.275 8.635,20.075 -2.235,20.075 -2.235,7.875 9.037,7.875 9.035,20.475 -2.635,20.475 -2.635,7.475 9.437,7.475 9.435,20.875 -3.035,20.875 -3.035,7.075 9.837,7.075 9.837,13.035 pad.0@10.089,13.035 pad.0@10.114,13.035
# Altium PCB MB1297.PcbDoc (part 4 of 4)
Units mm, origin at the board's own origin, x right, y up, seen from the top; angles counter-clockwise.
Board outline 90.1 x 62.11 mm, 4 copper layers (Top Layer, GND, POWER+GND, Bottom Layer), stack 0.778 mm thick; 235 components, 174 nets, 1727 pads, 1 vias.

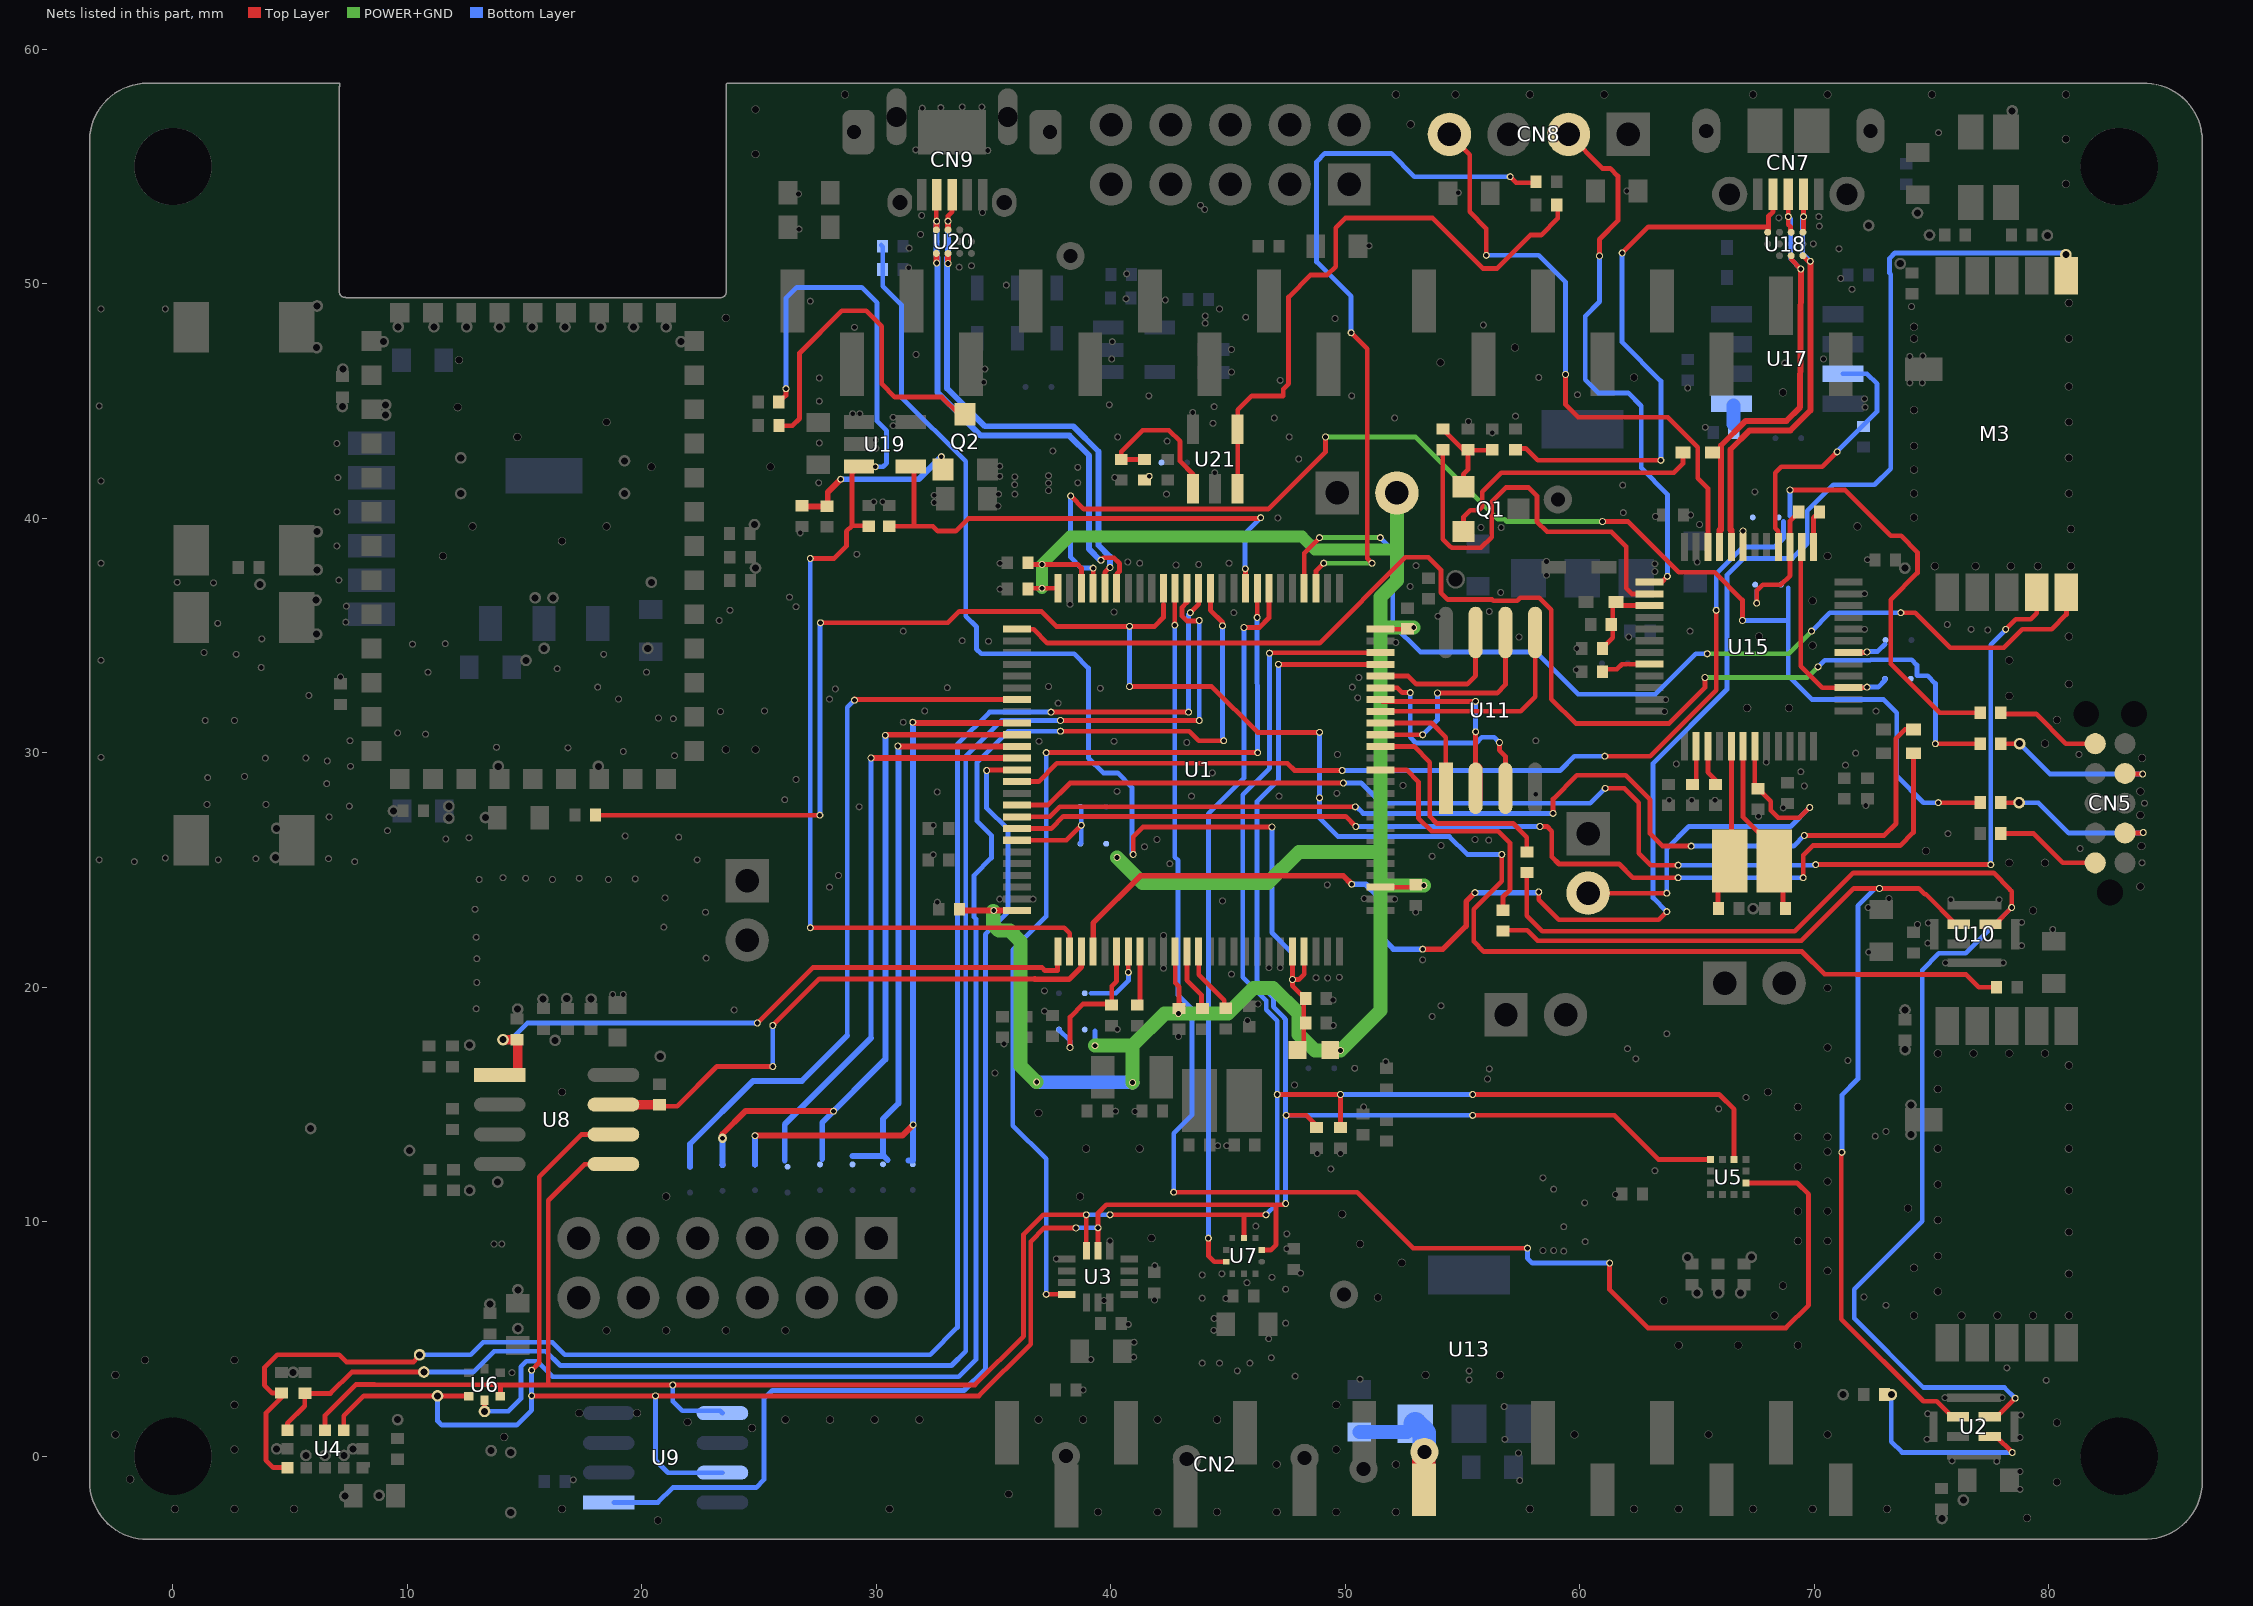
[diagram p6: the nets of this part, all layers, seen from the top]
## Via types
v1: diameter 0.4, hole 0.2, Top Layer to Bottom Layer, tented both sides, 1 vias

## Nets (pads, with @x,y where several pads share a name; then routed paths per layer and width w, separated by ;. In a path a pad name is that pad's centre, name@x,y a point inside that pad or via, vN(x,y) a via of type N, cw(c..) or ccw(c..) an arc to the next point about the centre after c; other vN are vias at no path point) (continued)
NetM3_1: M3.1 pad.46@63.708,23.22 pad.47@55.53,24.033 pad.49@58.247,24.059 pad.86@50.272,24.389 pad.91@53.294,21.62 pad.108@80.726,51.237 U1.4 | length 73.4
  Top Layer w0.204: pad.49@58.247,24.059 58.247,23.728 59.097,22.879 63.367,22.879 pad.46@63.708,23.22
  Top Layer w0.24: U1.4@39.244,21.516 39.244,22.734 41.255,24.744 49.916,24.744 pad.86@50.272,24.389 ; pad.91@53.294,21.62 54.158,21.62 55.149,22.611 55.149,23.652 pad.47@55.53,24.033
  Bottom Layer w0.204: pad.46@63.708,23.22 63.124,23.805 63.124,29.545 66.274,32.695 66.274,37.572 66.985,38.283 69.068,38.283 69.703,38.918 69.703,40.315 70.814,41.426 72.567,41.426 73.259,42.118 73.259,50.398 73.211,50.445 73.211,51.087 73.433,51.31 80.653,51.31 pad.108@80.726,51.237
  Bottom Layer w0.24: pad.86@50.272,24.389 50.871,24.389 51.366,23.893 51.366,22.304 52.05,21.62 pad.91@53.294,21.62 ; pad.47@55.53,24.033 58.222,24.033 pad.49@58.247,24.059
NetM3_10: M3.10 pad.23@78.161,35.26 pad.28@61.083,28.48 pad.29@64.191,25.202 pad.31@77.526,25.227 pad.32@70.058,25.227 pad.135@49.916,28.707 U1.91 | length 57.9
  Top Layer w0.204: U1.91@35.994,27.766 37.316,27.766 38.258,28.707 pad.135@49.916,28.707 ; pad.28@61.083,28.48 61.903,28.48 62.515,27.869 62.515,25.71 63.023,25.202 pad.29@64.191,25.202 ; pad.32@70.058,25.227 pad.31@77.526,25.227 ; pad.23@78.161,35.26 78.593,35.692 79.228,35.692 79.482,35.946 M3.10@79.482,36.848
  Bottom Layer w0.204: pad.135@49.916,28.707 50.678,28.707 51.542,27.843 60.446,27.843 pad.28@61.083,28.48 ; pad.29@64.191,25.202 pad.32@70.033,25.202 ; pad.31@77.526,25.227 77.526,34.6 78.161,35.235 pad.23@78.161,35.26
NetM3_11: M3.11 pad.50@48.9,39.172 pad.244 pad.245 pad.246 pad.247 U1.54 | length 42.5
  Top Layer w0.204: U1.54@48.244,37.016 48.244,38.515 pad.50@48.9,39.172 ; pad.245@73.691,35.971 74.3,35.971 75.799,34.473 78.085,34.473 78.872,35.26 80.117,35.26 80.752,35.895 M3.11@80.752,36.848
  POWER+GND w0.204: pad.50@48.9,39.172 pad.244@51.491,39.172 ; pad.247@65.436,34.219 68.915,34.219 pad.246@69.881,35.184
  Bottom Layer w0.204: pad.244@51.491,39.172 52.024,38.638 52.024,35.463 53.193,34.295 58.12,34.295 59.924,32.491 63.226,32.491 64.953,34.219 pad.247@65.436,34.219 ; pad.246@69.881,35.184 70.668,35.971 pad.245@73.691,35.971
NetQ1_1: Q1.1 R45.2 R46.2 R48.2 | length 4
  Top Layer w0.204: R45.2@54.158,43.803 54.158,43.794 R46.2@55.225,42.728 ; Q1.1@55.034,41.341 55.034,41.876 55.225,42.067 R46.2@55.225,42.728 ; R48.2@56.094,42.9 55.225,42.9 R46.2@55.225,42.728
NetQ1_2: Q1.2 R50.1 | length 11.8
  Top Layer w0.204: Q1.2@55.034,39.441 55.034,40.047 55.326,40.34 55.682,40.34 55.834,40.492 55.834,41.127 56.647,41.94 64.013,41.94 64.394,42.321 R50.1@64.394,42.804
NetQ2_1: pad.145@28.479,41.661 pad.146@32.771,42.626 Q2.1 R57.2 R59.2 | length 7
  Top Layer w0.254: R59.2@27.049,40.5 27.925,40.5 27.925,41.107 pad.145@28.479,41.661
  Bottom Layer w0.254: pad.145@28.479,41.661 31.806,41.661 pad.146@32.771,42.626
NetQ2_3: Q2.3 R55.1 | length 14.9
  Top Layer w0.204: R55.1@25.845,43.947 26.421,43.947 26.726,44.252 26.726,47.046 28.529,48.849 29.571,48.849 30.231,48.189 30.231,45.725 30.79,45.166 32.797,45.166 33.533,44.429 Q2.3@33.787,44.429
NetR1_2: pad.32@14.077,17.759 pad.58@24.923,18.471 R1.2 U1.1 U8.1 | length 28.7
  Top Layer w0.204: pad.58@24.923,18.471 27.285,20.833 37.064,20.833 37.191,20.706 37.724,20.706 37.724,21.496 U1.1@37.744,21.516
  Top Layer w0.4: U8.1@13.938,16.261 14.737,16.261 14.712,16.286 14.712,17.734 14.686,17.759 pad.32@14.077,17.759
  Bottom Layer w0.204: 14.407,17.759 15.118,18.471 pad.58@24.923,18.471
  Bottom Layer w0.24: pad.32@14.077,17.759 14.407,17.759
NetR4_2: pad.59@25.583,18.369 pad.60@25.583,16.616 R4.2 U1.3 U8.7 | length 24.1
  Top Layer w0.204: R4.2@20.757,15.118 20.95,14.925 21.504,14.925 23.195,16.616 pad.60@25.583,16.616 ; pad.59@25.583,18.369 27.565,20.351 36.758,20.351
  Top Layer w0.24: 36.758,20.351 36.775,20.333 38.215,20.333 38.744,20.862 U1.3@38.744,21.516
  Top Layer w0.4: U8.7@18.788,14.991 R4.2@20.63,14.991
  Bottom Layer w0.204: pad.60@25.583,16.616 pad.59@25.583,18.369
NetR5_1: R5.1 U1.12 | length 2.5
  Top Layer w0.204: U1.12@43.244,21.516 43.244,20.291 43.871,19.664 R5.1@43.871,19.283
NetR6_1: pad.165 pad.166 R6.1 U2.3 U10.3 | length 56.5
  Top Layer w0.2: R6.1@57.739,24.694 57.739,23.043 58.4,22.382 69.169,22.382 71.659,24.871 77.653,24.871 78.339,24.186 78.339,24.16 78.415,24.084 pad.166@78.415,23.398 77.707,22.691 U10.3@77.515,22.691 ; U2.3@77.482,1.687 77.785,1.687 pad.165@78.567,2.469
  Bottom Layer w0.2: pad.166@78.415,23.398 76.459,21.442 75.316,21.442 74.605,20.731 74.605,10.012 71.709,7.117 71.709,5.872 74.656,2.926 78.11,2.926 pad.165@78.567,2.469
NetR6_2: R6.2 U1.40 | length 9.6
  Top Layer w0.204: U1.40@51.494,30.266 52.929,30.266 53.599,29.596 53.599,27.284 53.904,26.98 57.155,26.98 57.739,26.395 R6.2@57.739,25.964
NetR7_1: R7.1 U1.13 | length 2.7
  Top Layer w0.204: U1.13@43.744,21.516 43.744,20.528 44.836,19.436 R7.1@44.836,19.283
NetR10_2: pad.3@20.579,2.57 pad.9@47.148,33.766 pad.11@47.452,10.774 pad.14@11.283,2.57 pad.15@15.296,2.57 pad.16@15.296,3.662 pad.17@39.451,9.737 pad.18@38.512,9.733 pad.20@47.478,14.534 pad.151 R10.2 U1.47 U3.13 U4.10 U5.1 U6.2 U7.2 U8.6 U9.7 | length 121.8
  Top Layer w0.204: U4.10@7.282,1.11 7.282,1.719 8.133,2.57 pad.14@11.283,2.57 12.597,2.57 U6.2@12.614,2.553 ; pad.15@15.296,2.57 pad.3@20.579,2.57 34.371,2.57 36.582,4.781 36.582,9.15 37.165,9.733 pad.18@38.512,9.733 ; pad.16@15.296,3.662 15.626,3.993 15.626,11.917 17.43,13.721 U8.6@18.788,13.721 ; U3.13@39.451,8.75 pad.17@39.451,9.737 39.451,10.368 39.807,10.724 46.944,10.724 ; U7.2@46.437,8.789 46.813,8.789 47.046,9.022 47.046,10.724 pad.11@47.402,10.724 ; pad.9@47.148,33.766 U1.47@51.494,33.766 ; pad.20@47.478,14.534 48.341,14.534 R10.2@48.85,14.025 ; pad.151@55.428,14.534 61.473,14.534 63.353,12.654 U5.1@65.579,12.654
  Bottom Layer w0.204: pad.14@11.283,2.57 11.283,1.503 11.461,1.326 14.661,1.326 15.296,1.961 pad.15@15.296,2.57 pad.16@15.296,3.662 ; pad.3@20.579,2.57 20.579,-0.173 21.113,-0.706 U9.7@23.436,-0.706 ; pad.18@38.516,9.737 pad.17@39.451,9.737 ; pad.9@47.148,33.766 47.148,28.834 46.233,27.919 46.233,20.255 46.931,19.557 46.931,19.168 47.401,18.698 47.401,18.668 47.449,18.62 pad.11@47.449,10.778 ; pad.20@47.576,14.534 pad.151@55.428,14.534
NetR11_2: pad.2@21.316,3.036 pad.8@46.767,34.244 pad.12@46.614,10.292 pad.13@39.959,10.292 pad.14@38.951,10.292 pad.19@47.095,15.423 pad.152@55.428,15.423 pad.153@49.789,15.423 R11.2 U1.48 U3.14 U4.9 U5.11 U6.4 U7.4 U8.5 U9.5 | length 117.5
  Top Layer w0.204: U4.9@6.482,1.11 6.482,1.732 7.803,3.053 8.59,3.053 8.596,3.047 13.975,3.047 13.964,3.036 ; U6.4@13.964,2.553 13.964,3.036 ; U8.5@18.788,12.451 17.557,12.451 16.007,10.901 16.007,3.036 ; U3.14@38.951,8.75 pad.14@38.951,10.292 37.115,10.292 36.276,9.454 36.276,5.11 34.202,3.036 pad.2@21.316,3.036 16.007,3.036 ; pad.13@39.959,10.292 45.674,10.292 ; U7.4@45.674,9.302 45.674,10.292 ; pad.12@46.614,10.292 45.674,10.292 ; pad.8@46.767,34.244 46.788,34.266 U1.48@51.494,34.266 ; pad.19@47.095,15.423 pad.153@49.789,15.423 R11.2@49.789,14.015 ; pad.152@55.428,15.423 65.944,15.423 66.579,14.788 U5.11@66.579,12.654 ; 13.964,3.036 16.007,3.036
  Bottom Layer w0.204: pad.2@21.316,3.036 21.316,2.334 21.716,1.933 23.336,1.933 U9.5@23.436,1.834 ; pad.14@38.951,10.292 pad.13@39.959,10.292 ; pad.12@46.614,10.292 47.095,10.773 pad.19@47.095,15.423 47.095,18.571 46.625,19.041 46.625,19.43 45.624,20.432 45.624,28.199 46.767,29.342 pad.8@46.767,34.244 ; pad.153@49.789,15.423 pad.152@55.428,15.423
NetR12_1: R12.1 U1.8 | length 2.3
  Top Layer w0.204: R12.1@41.125,19.24 41.244,19.359 U1.8@41.244,21.516
NetR13_1: pad.167 pad.168 R13.1 U2.4 U10.4 | length 46.8
  Top Layer w0.2: 74.453,24.211 74.707,23.957 74.763,23.957 76.03,22.691 U10.4@76.165,22.691
  Top Layer w0.204: R13.1@56.944,22.425 57.75,22.425 58.199,21.976 69.449,21.976 71.684,24.211 pad.168@72.776,24.211 74.453,24.211 ; pad.167@71.176,12.959 71.151,12.933 71.151,5.847 74.656,2.342 75.222,2.342 75.877,1.687 U2.4@76.132,1.687
  Bottom Layer w0.204: pad.167@71.176,12.959 71.176,15.397 71.862,16.083 71.862,23.467 72.606,24.211 pad.168@72.776,24.211
NetR13_2: R13.2 U1.38 | length 10.5
  Top Layer w0.204: U1.38@51.494,29.266 52.609,29.266 53.117,28.758 53.117,27.208 53.675,26.649 56.52,26.649 57.027,26.143 57.027,24.159 56.723,23.856 R13.2@56.723,23.474
NetR14_2: pad.17@10.699,3.586 pad.25@43.769,35.641 pad.28@37.851,31.374 pad.29@43.769,31.374 R14.2 U1.64 U4.7 | length 73.7
  Top Layer w0.204: U4.7@4.882,1.11 4.882,1.402 5.619,2.138 5.619,2.675 6.714,2.675 7.625,3.586 pad.17@10.699,3.586 ; pad.28@37.851,31.374 pad.29@43.769,31.374 ; U1.64@43.244,37.016 43.244,36.411 43.034,36.201 43.034,35.825 43.242,35.617 43.746,35.617 pad.25@43.769,35.641
  Bottom Layer w0.204: pad.17@10.699,3.586 12.807,3.586 13.696,4.475 15.906,4.475 16.515,3.866 33.203,3.866 33.814,4.477 33.814,29.851 35.337,31.374 pad.28@37.851,31.374 ; pad.29@43.769,31.374 pad.25@43.769,35.641
NetR15_2: pad.18@10.521,4.323 pad.26@43.388,35.971 pad.27@37.445,31.729 pad.30@43.312,31.729 R15.2 U1.63 U4.5 | length 77.3
  Top Layer w0.204: R15.2@4.628,2.494 3.968,1.834 3.968,-0.173 4.285,-0.49 U4.5@4.882,-0.49 ; R15.2@4.628,2.689 4.236,2.689 3.9,3.025 3.9,3.775 4.45,4.325 7.09,4.325 7.397,4.018 10.267,4.018 pad.18@10.521,4.323 ; pad.27@37.445,31.729 pad.30@43.312,31.729 ; pad.26@43.388,35.971 43.744,36.327 U1.63@43.744,37.016
  Bottom Layer w0.204: pad.18@10.521,4.323 12.693,4.323 13.226,4.856 16.185,4.856 16.718,4.323 32.289,4.323 33.457,5.491 33.457,30.358 34.829,31.729 pad.27@37.445,31.729 ; pad.30@43.312,31.729 43.312,35.895 pad.26@43.388,35.971
NetR16_1: pad.172 R16.1 SB1.2
NetR16_2: R16.2 R38.2 U21.1 | length 6.7
  Top Layer w0.204: R16.2@41.433,42.507 R38.2@40.442,42.507 40.442,42.842 41.35,43.75 42.475,43.75 42.95,43.275 42.95,42.429 43.503,41.877 U21.1@43.503,41.254
NetR18_1: R18.1 U21.3 U21.4 | length 26.1
  Top Layer w0.204: U21.3@45.408,41.254 U21.4@45.408,43.794 45.408,44.62 46.005,45.217 47.351,45.217 47.351,45.507 47.576,45.732 47.576,49.43 48.519,50.373 49.23,50.373 49.586,50.729 49.586,52.38 50.01,52.804 53.712,52.804 55.863,50.652 56.469,50.652 57.892,52.075 58.349,52.075 59.06,52.786 R18.1@59.06,53.37
NetR20_1: pad.51@49.078,38.079 pad.76@51.135,38.079 pad.77@57.028,54.564 pad.81@50.246,47.909 R20.1 U1.53 | length 31.4
  Top Layer w0.204: U1.53@48.744,37.016 48.744,37.745 pad.51@49.078,38.079 ; pad.81@50.246,47.909 50.932,47.223 50.932,38.283 pad.76@51.135,38.079 ; pad.77@57.028,54.564 57.282,54.31 R20.1@58.135,54.31
  POWER+GND w0.204: pad.51@49.078,38.079 pad.76@51.135,38.079
  Bottom Layer w0.204: pad.81@50.246,47.909 50.246,49.459 48.773,50.932 48.773,55.199 49.129,55.555 51.948,55.555 52.939,54.564 pad.77@57.028,54.564
NetR21_1: pad.53@56.673,25.659 pad.106@27.59,27.335 pad.107@27.615,35.539 pad.184 pad.186 pad.187 pad.193 R21.1 R22.1 U1.66 | length 84.4
  Top Layer w0.204: R21.1@18.022,27.335 pad.106@27.59,27.335 ; pad.107@27.615,35.539 33.049,35.539 33.533,36.023 37.038,36.023 37.674,35.387 pad.184@40.798,35.387 41.864,35.387 42.244,35.767 42.244,36.327 ; pad.193@40.798,32.822 44.303,32.822 46.259,30.866 pad.187@48.9,30.866 ; pad.53@56.673,25.659 56.673,24.516 55.479,23.322 55.479,21.95 55.911,21.519 69.474,21.519 70.439,20.553 71.786,20.553 71.801,20.538 76.474,20.538 77.018,19.995 R22.1@77.772,19.995
  Bottom Layer w0.204: pad.106@27.59,27.335 pad.107@27.59,35.514 ; pad.193@40.798,32.822 pad.184@40.798,35.387 ; pad.187@48.9,30.866 pad.186@48.9,28.072 48.9,27.208 49.688,26.421 54.437,26.421 55.199,25.659 pad.53@56.673,25.659
NetR29_1: R29.1 U15.44 | length 2
  Top Layer w0.204: R29.1@61.04,33.558 61.583,33.558 61.798,33.773 U15.44@62.964,33.773
NetR31_1: R31.1 U15.2 | length 1.7
  Top Layer w0.204: R31.1@64.801,28.639 64.964,28.802 U15.2@64.964,30.273
NetR32_2: pad.75@75.164,30.383 pad.239 pad.241 R32.2 SB6.1 U1.76 | length 53.4
  Top Layer w0.204: U1.76@35.994,35.266 36.703,35.266 37.292,34.676 48.9,34.676 52.555,38.332 53.543,38.332 54.075,37.8 54.075,36.825 54.37,36.53 56.266,36.53 56.315,36.481 57.335,36.481 57.46,36.606 58.273,36.606 58.781,36.098 58.781,32.288 59.822,31.247 63.81,31.247 65.334,32.771 pad.239@65.334,33.203 ; pad.75@75.164,30.383 R32.2@77.073,30.383 R32.2@77.124,30.383
  POWER+GND w0.204: pad.239@65.334,33.203 69.703,33.203 pad.241@70.16,33.66
  Bottom Layer w0.204: pad.241@70.16,33.66 70.441,33.941 72.389,33.941 72.413,33.965 74.148,33.965 74.376,33.736 74.376,33.279 74.834,33.279 75.164,32.949 pad.75@75.164,30.383
NetR33_2: pad.74@75.291,27.869 pad.99@39.244,37.872 pad.212 pad.213 pad.215 pad.216 R33.2 SB5.1 U1.72 | length 56.7
  Top Layer w0.204: pad.212@38.283,40.95 38.842,40.391 38.84,40.389 46.714,40.389 49.154,42.829 pad.213@49.154,43.464 ; U1.72@39.244,37.016 pad.99@39.244,37.872 ; pad.215@60.965,39.857 62.057,39.857 64.216,37.698 65.745,37.698 66.934,36.509 pad.216@66.934,35.641 ; pad.74@75.291,27.869 R33.2@77.073,27.869 R33.2@77.124,27.869
  POWER+GND w0.204: pad.213@49.154,43.464 52.99,43.464 56.496,39.957 56.794,39.957 56.894,39.857 pad.215@60.965,39.857 pad.215@60.991,39.883
  Bottom Layer w0.204: pad.212@38.283,40.95 38.283,38.333 38.744,37.872 pad.99@39.244,37.872 ; pad.216@66.934,35.641 68.89,35.641 ; 68.89,37.038 68.89,35.641 ; pad.74@75.291,27.869 74.656,27.869 73.513,29.012 73.513,31.704 72.954,32.263 69.906,32.263 68.89,33.279 68.89,35.641
NetR35_2: pad.14@68.964,41.201 pad.43@61.067,29.85 pad.45@65.817,36.073 pad.136@49.865,29.24 R35.2 SB7.1 U1.89 | length 58.4
  Top Layer w0.204: U1.89@35.994,28.766 36.919,28.766 37.699,29.545 47.529,29.545 47.833,29.24 pad.136@49.865,29.24 ; pad.43@61.067,29.85 62.997,29.85 65.817,32.669 pad.45@65.817,36.073 ; pad.14@68.966,41.204 71.303,41.204 73.259,39.248 73.702,39.248 74.399,38.551 74.399,37.665 73.259,36.525 73.259,33.787 75.342,31.704 R35.2@77.073,31.704
  Bottom Layer w0.204: pad.136@49.865,29.24 59.162,29.24 59.771,29.85 pad.43@61.067,29.85 ; pad.45@65.817,36.073 65.817,37.626 66.964,38.773 68.314,38.773 68.687,39.146 68.687,39.857 ; 68.964,40.083 pad.14@68.964,41.201 pad.14@68.966,41.204
NetR36_1: R36.1 U15.3 | length 1.8
  Top Layer w0.204: U15.3@65.464,30.273 65.464,29.161 65.791,28.834 R36.1@65.791,28.639
NetR42_2: pad.33@58.298,26.853 pad.36@64.191,24.668 pad.37@69.525,24.668 pad.134@50.45,26.853 R42.2 U1.93 | length 44.9
  Top Layer w0.204: U1.93@35.994,26.766 37.46,26.766 37.979,27.284 50.018,27.284 pad.134@50.45,26.853 ; pad.33@58.298,26.853 58.603,26.853 58.806,26.649 58.806,25.557 59.111,25.252 61.676,25.252 62.261,24.668 pad.36@64.191,24.668 ; pad.37@69.525,24.668 69.525,25.633 69.931,26.04 73.665,26.04 74.224,26.599 R42.2@74.224,29.977
  Bottom Layer w0.204: pad.134@50.45,26.853 pad.33@58.298,26.853 ; pad.36@64.191,24.668 pad.37@69.525,24.668
NetR43_2: pad.38@69.576,26.472 pad.39@64.75,26.014 pad.40@58.857,27.411 pad.133@50.424,27.691 R43.2 U1.92 | length 45.8
  Top Layer w0.204: U1.92@35.994,27.266 37.401,27.266 37.826,27.691 pad.133@50.424,27.691 ; pad.40@58.857,27.411 58.857,28.021 59.873,29.037 61.956,29.037 62.997,27.996 62.997,26.548 63.531,26.014 pad.39@64.75,26.014 ; pad.38@69.576,26.472 72.979,26.472 73.487,26.98 73.487,30.612 73.868,30.993 R43.2@74.224,30.993
  Bottom Layer w0.204: pad.133@50.424,27.691 50.475,27.691 50.754,27.411 pad.40@58.857,27.411 ; pad.39@64.75,26.014 69.119,26.014 pad.38@69.576,26.472
NetR53_2: R53.2 U17.5 | length 0.8
  Bottom Layer w0.6: 66.553,44.023 U17.5@66.553,44.798
NetR56_1: pad.57@27.183,22.535 pad.115@27.183,38.283 pad.121@29.952,42.194 pad.144@26.142,45.522 R56.1 R58.2 U1.2 U19.3 | length 50.2
  Top Layer w0.204: R56.1@25.849,44.941 26.142,45.234 pad.144@26.142,45.522 ; pad.57@27.183,22.535 38.002,22.535 38.244,22.292 U1.2@38.244,21.516 ; pad.115@27.183,38.283 28.199,38.283 28.723,38.806 28.723,39.436 28.961,39.675 ; U19.3@29.258,42.209 28.961,41.912 28.961,39.675 ; R58.2@29.6,39.675 28.961,39.675
  Bottom Layer w0.204: pad.144@26.142,45.522 26.142,49.382 26.599,49.84 29.368,49.84 30.028,49.179 30.028,44.132 30.434,43.726 30.434,42.347 30.282,42.194 pad.121@29.952,42.194 ; pad.57@27.183,22.535 pad.115@27.183,38.283
NetR62_2: pad.131@46.386,40.022 pad.132@45.735,37.841 R62.2 U1.59 U19.4 | length 21.9
  Top Layer w0.204: R62.2@30.643,39.646 30.656,39.659 32.41,39.659 32.619,39.451 33.389,39.451 33.922,39.984 46.335,39.984 pad.131@46.386,40.035 ; U19.4@31.458,42.209 31.603,42.065 31.603,39.75 ; pad.132@45.725,37.851 pad.132@45.735,37.841 45.744,37.832 U1.59@45.744,37.016
  Bottom Layer w0.204: pad.132@45.725,37.851 45.725,39.349 46.386,40.01 pad.131@46.386,40.022 pad.131@46.386,40.035
NetR67_2: pad.45@73.284,2.621 pad.94@78.44,0.157 R67.2 U2.2 | length 8.6
  Top Layer w0.204: U2.2@77.482,0.837 77.761,0.837 pad.94@78.44,0.157
  Bottom Layer w0.204: pad.45@73.284,2.621 73.284,0.614 73.741,0.157 pad.94@78.44,0.157
NetSB3_1: pad.48@40.747,20.63 SB3.1 U1.7 | length 3.1
  Top Layer w0.204: U1.7@40.744,21.516 40.744,20.632 pad.48@40.747,20.63
  Bottom Layer w0.204: 39.147,19.741 40.213,19.741 40.747,20.274 pad.48@40.747,20.63
NetSB9_2: pad.54@38.74,26.903 SB9.2 SB13.2 U1.94 | length 4.6
  Top Layer w0.204: U1.94@35.994,26.266 38.102,26.266 pad.54@38.74,26.903
  Bottom Layer w0.204: SB9.2@38.699,26.116 38.74,26.157 pad.54@38.74,26.903 38.74,27.65 SB13.2@38.699,27.691
NetSB12_2: pad.132@30.917,30.282 SB12.2 SB14.2 U1.86 | length 24.4
  Top Layer w0.254: pad.132@30.933,30.266 U1.86@35.994,30.266
  Bottom Layer w0.254: 28.983,12.791 30.323,12.791 30.485,12.629 ; 30.282,12.797 30.282,14.387 30.942,15.047 30.942,30.256 pad.132@30.917,30.282
NetSB15_2: pad.2@28.174,14.711 pad.131@30.384,30.739 SB15.2 SB16.2 U1.85 | length 31.2
  Top Layer w0.254: v1(23.439,13.558) 23.439,13.735 24.415,14.711 pad.2@28.174,14.711 ; pad.131@30.384,30.739 30.461,30.766 U1.85@35.994,30.766
  Bottom Layer w0.254: SB16.2@23.439,12.416 v1(23.439,13.558) ; 27.691,12.679 27.691,14.229 30.384,16.921 pad.131@30.384,30.739
NetSB18_2: pad.0@24.825,13.666 pad.1@31.565,14.127 pad.130@31.552,31.298 SB18.2 SB19.2 U1.84 | length 31.5
  Top Layer w0.254: pad.0@24.825,13.666 31.105,13.666 pad.1@31.565,14.127 ; pad.130@31.552,31.298 31.647,31.266 U1.84@35.994,31.266
  Bottom Layer w0.254: SB18.2@24.825,12.441 pad.0@24.825,13.666 ; 31.363,12.613 31.567,12.613 pad.1@31.565,14.127 pad.130@31.552,31.298
NetSB20_1: pad.133@29.774,29.774 SB20.1 U1.87 | length 24.9
  Top Layer w0.254: pad.133@29.774,29.774 29.842,29.766 U1.87@35.994,29.766
  Bottom Layer w0.204: 29.774,17.836 pad.133@29.774,29.774
  Bottom Layer w0.254: 26.091,12.603 26.091,14.153 29.774,17.836
NetSB21_1: pad.134@29.063,32.237 SB21.1 U1.82 | length 31
  Top Layer w0.204: pad.134@29.091,32.266 U1.82@35.994,32.266
  Top Layer w0.254: pad.134@29.063,32.237 pad.134@29.091,32.266
  Bottom Layer w0.204: 28.758,17.937 28.758,31.933 pad.134@29.063,32.237
  Bottom Layer w0.254: SB21.1@22.052,12.341 22.052,13.314 24.745,16.007 26.828,16.007 28.758,17.937
NetU1_41: pad.58@53.929,32.542 pad.59@53.294,30.764 U1.41 U11.6 | length 8.2
  Top Layer w0.204: U1.41@51.494,30.766 53.293,30.766 pad.59@53.294,30.764 ; pad.58@53.929,32.542 56.469,32.542 56.825,32.898 U11.6@56.825,34.231
  Bottom Layer w0.204: pad.59@53.294,30.764 53.929,31.399 pad.58@53.929,32.542
NetU1_42: U1.42 U11.1 | length 4.3
  Top Layer w0.204: U1.42@51.494,31.266 53.682,31.266 54.285,30.663 U11.1@54.285,29.381
NetU1_43: U1.43 U11.5 | length 8.7
  Top Layer w0.204: U1.43@51.494,31.766 57.471,31.766 58.095,32.39 U11.5@58.095,34.231
NetU1_44: pad.62@55.555,30.891 pad.63@55.553,32.188 U1.44 U11.2 | length 9.1
  Top Layer w0.204: U1.44@51.494,32.266 51.571,32.188 pad.63@55.553,32.188 ; U11.2@55.555,28.986 pad.62@55.555,30.891 ; U11.2@55.555,29.484 55.637,29.484 55.753,29.368 U11.2@55.753,27.818
  Bottom Layer w0.204: pad.63@55.553,32.188 55.553,30.893 pad.62@55.555,30.891
NetU1_45: pad.60@52.768,32.561 pad.61@56.571,30.434 U1.45 U11.3 | length 9.1
  Top Layer w0.204: U1.45@51.494,32.766 52.219,32.766 52.424,32.561 pad.60@52.768,32.561 ; pad.61@56.571,30.434 56.571,30.104 56.825,29.85 U11.3@56.825,28.808
  Bottom Layer w0.204: pad.60@52.768,32.561 52.768,30.656 53.013,30.41 55.575,30.41 55.82,30.656 56.349,30.656 pad.61@56.571,30.434
NetU1_46: U1.46 U11.7 | length 5.3
  Top Layer w0.204: U1.46@51.494,33.266 52.685,33.266 53.027,32.923 55.199,32.923 55.555,33.279 U11.7@55.555,34.231
NetU1_57: pad.39@44.158,9.293 pad.40@45.674,35.336 U1.57 U7.7 | length 30.8
  Top Layer w0.204: pad.39@44.158,9.293 44.158,8.539 44.408,8.289 U7.7@44.912,8.289 ; pad.40@45.674,35.336 46.335,35.336 46.744,35.745 U1.57@46.744,37.016
  Bottom Layer w0.204: pad.39@44.158,9.293 44.158,27.395 45.674,28.911 pad.40@45.674,35.336
NetU1_58: pad.23@37.242,6.9 pad.24@46.238,35.768 pad.31@46.259,30.002 pad.32@37.242,30.002 U1.58 U3.4 | length 41.1
  Top Layer w0.204: pad.23@37.242,6.9 U3.4@38.121,6.9 ; pad.32@37.242,30.002 pad.31@46.259,30.002 ; pad.24@46.238,35.768 46.244,36.033 U1.58@46.244,37.016
  Bottom Layer w0.204: pad.23@37.242,6.9 37.242,12.676 35.819,14.098 35.819,21.595 37.242,23.017 pad.32@37.242,30.002 ; pad.24@46.238,35.768 pad.31@46.259,30.053
NetU1_62: pad.15@13.289,1.91 pad.35@37.851,30.917 pad.36@44.76,35.412 pad.37@44.811,30.51 U1.62 U6.3 | length 67.7
  Top Layer w0.204: pad.15@13.289,1.91 U6.3@13.289,2.378 ; pad.35@37.851,30.917 43.338,30.917 43.744,30.51 pad.37@44.811,30.51 ; U1.62@44.244,37.016 44.244,36.081 44.76,35.565 pad.36@44.76,35.412
  Bottom Layer w0.204: pad.15@13.289,1.91 14.305,1.91 14.839,2.443 14.839,3.814 15.067,4.042 15.532,4.042 16.191,3.383 21.162,3.383 21.169,3.39 21.462,3.39 21.469,3.383 33.508,3.383 34.244,4.12 34.244,22.922 34.169,22.998 34.169,24.778 34.905,25.514 34.905,26.472 34.295,27.081 34.295,29.596 35.616,30.917 pad.35@37.851,30.917 ; pad.37@44.76,30.561 pad.36@44.76,35.412
NetU1_65: pad.155@42.728,35.438 pad.156@42.677,11.257 pad.157 pad.159 U1.65 U5.8 | length 64.8
  Top Layer w0.204: pad.156@42.677,11.257 50.5,11.257 52.888,8.869 pad.157@57.765,8.869 ; pad.155@42.728,35.438 42.728,37 U1.65@42.744,37.016 ; pad.159@61.27,8.234 61.27,7.091 62.896,5.466 68.788,5.466 69.754,6.431 69.754,11.162 69.262,11.654 U5.8@67.079,11.654
  Bottom Layer w0.204: pad.156@42.677,11.257 42.677,13.772 43.465,14.559 43.465,19.055 42.866,19.654 42.866,25.412 42.728,25.55 pad.155@42.728,35.438 ; pad.157@57.765,8.869 57.765,8.438 57.968,8.234 pad.159@61.27,8.234
NetU1_88: pad.156@34.702,29.24 U1.88 U9.1 | length 47.8
  Top Layer w0.204: pad.156@34.702,29.24 34.727,29.266 U1.88@35.994,29.266
  Bottom Layer w0.204: U9.1@18.801,-1.976 20.681,-1.976 21.316,-1.341 24.872,-1.341 25.202,-1.011 25.202,2.443 25.558,2.799 33.736,2.799 34.651,3.713 34.651,22.257 35.614,23.22 35.614,26.727 34.702,27.64 pad.156@34.702,29.24
OSC_IN: C52.2 U15.5 X3.2 | length 7.2
  Top Layer w0.204: C52.2@65.893,23.35 65.893,24.882 X3.2@66.391,25.379 66.464,25.452 U15.5@66.464,30.273
OSC_OUT: C51.2 U15.6 X3.1 | length 7.6
  Top Layer w0.204: U15.6@66.964,30.273 66.964,27.255 68.291,25.928 X3.1@68.291,25.379 68.669,25.001 C51.2@68.669,23.425
PWR_ENN: pad.20@70.973,42.829 R51.1 U15.28 U17.3 | length 11.5
  Top Layer w0.204: U15.28@68.464,38.773 68.464,39.447 68.331,39.579 68.331,41.94 68.585,42.194 70.338,42.194 pad.20@70.973,42.829
  Bottom Layer w0.204: pad.20@70.96,42.842 72.675,44.556 72.675,45.725 72.243,46.157 U17.3@71.214,46.157
PWR_EXT: R27.1 R28.2 R30.2 U15.39 | length 3.6
  Top Layer w0.204: R27.1@61,34.396 61,34.5 61.4,34.9 61.4,36.273 U15.39@62.964,36.273
STM_JTCK: CN8.2 pad.70@60.838,51.186 pad.71@63.734,37.523 U15.37 | length 23.6
  Top Layer w0.204: CN8.2@59.517,56.367 60.965,54.92 61.295,54.92 61.626,54.589 61.626,52.684 60.838,51.897 pad.70@60.838,51.186 ; U15.37@62.964,37.273 63.484,37.273 pad.71@63.734,37.523
  Bottom Layer w0.204: pad.70@60.838,51.186 60.838,49.23 60.229,48.62 60.229,45.903 60.787,45.344 62.057,45.344 62.616,44.785 62.616,42.143 63.734,41.026 pad.71@63.734,37.523
STM_JTMS: CN8.4 pad.68@59.39,46.131 pad.69@56.012,51.211 U15.34 | length 25.7
  Top Layer w0.204: CN8.4@54.437,56.367 55.301,55.504 55.301,53.065 56.012,52.354 pad.69@56.012,51.211 ; pad.68@59.39,46.131 59.39,44.836 59.924,44.302 63.756,44.302 65.029,43.029 65.029,41.712 65.464,41.277 U15.34@65.464,38.773
  Bottom Layer w0.204: pad.69@56.012,51.211 58.247,51.211 59.39,50.068 pad.68@59.39,46.131
STM_RST: C54.1 JP8.2 pad.34@63.708,24.008 pad.35@69.804,27.665 U15.7 | length 17.1
  Top Layer w0.204: JP8.2@60.356,24.008 pad.34@63.708,24.008 ; U15.7@67.464,30.273 67.464,28.601 C54.1@67.6,28.465 68.146,27.919 68.146,27.536 68.457,27.225 69.364,27.225 pad.35@69.804,27.665
  Bottom Layer w0.204: pad.34@63.708,24.008 63.708,25.913 64.648,26.853 68.992,26.853 pad.35@69.804,27.665
T_JTCK: pad.71@72.243,32.796 SB6.2 U15.15 U15.26 | length 9.3
  Top Layer w0.204: U15.26@69.464,38.773 69.423,38.733 69.423,33.685 70.335,32.773 U15.15@71.464,32.773 72.22,32.773 pad.71@72.243,32.796
  Bottom Layer w0.204: pad.71@72.243,32.796 72.725,32.796 73.014,33.085 SB6.2@73.014,33.152
T_JTMS: pad.50@67.544,36.378 R39.2 SB5.2 U15.27 | length 5.6
  Top Layer w0.204: pad.50@67.544,36.378 67.544,36.911 67.798,37.165 68.577,37.165 68.964,37.551 U15.27@68.964,38.773 68.964,39.888 R39.2@69.339,40.264
  Bottom Layer w0.204: pad.50@67.544,36.378 67.544,36.911
T_NRST: pad.70@72.243,34.295 SB8.2 U15.18 | length 1.7
  Top Layer w0.204: U15.18@71.464,34.273 pad.70@72.221,34.273
  Bottom Layer w0.204: pad.70@72.243,34.295 72.268,34.32 72.71,34.32 73.014,34.625
T_SWDIO_IN: R39.1 U15.25 | length 1.6
  Top Layer w0.204: U15.25@69.964,38.773 69.964,40.008 R39.1@70.219,40.264
T_SWO: pad.13@66.96,39.451 SB7.2 U15.31
TAG_NRST: CN5.10 R34.1 | length 4.5
  Top Layer w0.204: R34.1@78.004,26.548 79.355,26.548 80.599,25.303 CN5.10@81.979,25.303
TAG_SWCLK: CN5.4 pad.0@84.003,29.088 pad.50@78.758,30.383 R32.1 | length 7.3
  Top Layer w0.204: R32.1@78.004,30.383 pad.50@78.758,30.383 ; CN5.4@83.249,29.113 83.274,29.088 pad.0@84.003,29.088
  Bottom Layer w0.204: pad.50@78.758,30.383 80.053,29.088 pad.0@84.003,29.088
TAG_SWDIO: CN5.2 pad.1@84.028,26.599 pad.51@78.733,27.869 R33.1 | length 7.4
  Top Layer w0.204: R33.1@78.004,27.869 pad.51@78.733,27.869 ; CN5.2@83.249,26.573 84.003,26.573 pad.1@84.028,26.599
  Bottom Layer w0.204: pad.51@78.733,27.869 79.558,27.869 80.853,26.573 84.003,26.573 pad.1@84.028,26.599
TAG_SWO: CN5.6 R35.1 | length 4.6
  Top Layer w0.204: R35.1@77.953,31.653 79.456,31.653 80.726,30.383 CN5.6@81.979,30.383
USB_N: CN9.2 pad.1@32.568,52.667 pad.2@32.568,50.881 pad.9@39.578,38.206 U1.70 U20.D1 U20.D3 | length 22.9
  Top Layer w0.204: pad.1@32.555,52.575 32.555,53.768 CN9.2@32.578,53.792 ; pad.9@39.578,38.206 39.682,38.31 40.128,38.31 40.367,38.071 40.367,37.733 40.261,37.626
  Top Layer w0.254: U20.D3@32.555,51.295 32.555,50.894 pad.2@32.568,50.881 ; U20.D1@32.555,52.295 pad.1@32.555,52.575
  Bottom Layer w0.254: pad.1@32.568,52.667 32.568,51.16 32.607,51.121 32.607,45.368 34.458,43.517 38.23,43.517 39.07,42.677 39.07,38.679 pad.9@39.553,38.196
USB_P: CN9.3 pad.6@33.051,52.667 pad.7@33.055,50.86 pad.10@39.959,37.902 U1.71 U20.C1 U20.C3 | length 22.9
  Top Layer w0.204: pad.6@33.055,52.575 33.055,52.892 33.228,53.065 CN9.3@33.228,53.792 ; U1.71@39.744,37.016 39.744,37.686 pad.10@39.959,37.902
  Top Layer w0.254: pad.7@33.051,50.856 pad.7@33.055,50.86 U20.C3@33.055,51.295 ; U20.C1@33.055,52.295 pad.6@33.055,52.575
  Bottom Layer w0.254: pad.6@33.051,52.667 33.051,51.135 33.011,51.096 33.011,45.535 34.625,43.921 38.397,43.921 39.474,42.844 39.474,38.846 39.957,38.363 39.957,37.904 pad.10@39.959,37.902
USB_RENUMN: R45.1 U15.38 | length 18.1
  Top Layer w0.204: R45.1@54.158,42.728 54.158,39.103 54.474,38.787 54.493,38.787 54.54,38.74 55.784,38.74 56.241,39.197 56.241,40.696 56.85,41.305 57.816,41.305 58.171,40.95 58.171,39.857 58.603,39.426 61.346,39.426 61.981,38.791 61.981,37.013 62.22,36.773 U15.38@62.964,36.773
USB_STLK_ID: CN7.4 pad.85@61.803,51.313 pad.86@63.456,42.469 R54.1 U18.A3 | length 24.6
  Top Layer w0.204: R54.1@57.257,42.974 57.696,42.974 58.201,42.469 pad.86@63.456,42.469 ; pad.85@61.803,51.313 62.913,52.422 68.013,52.422 U18.A3@68.013,52.194 68.052,52.233 68.052,52.888 68.24,53.076 CN7.4@68.24,53.818
  Bottom Layer w0.204: pad.85@61.803,51.313 61.803,47.503 63.456,45.85 pad.86@63.456,42.469
USB_STLK_N: CN7.2 pad.12@69.54,52.862 pad.14@69.83,50.957 U15.32 U18.D1 U18.D3 | length 18.6
  Top Layer w0.204: U18.D1@69.513,51.194 69.75,50.957 pad.14@69.83,50.957 ; U18.D3@69.54,52.303 pad.12@69.54,52.862 CN7.2@69.54,53.818
  Top Layer w0.254: U15.32@66.464,38.773 66.464,39.502 66.426,39.502 66.426,42.931 67.241,43.746 68.981,43.746 69.83,44.595 pad.14@69.83,50.957
  Bottom Layer w0.204: pad.12@69.54,52.862 69.5,52.822 69.5,51.287 pad.14@69.83,50.957
USB_STLK_P: CN7.3 pad.11@68.89,52.862 pad.13@69.423,50.627 R50.2 U15.33 U18.C1 U18.C3 | length 19.2
  Top Layer w0.204: CN7.3@68.89,53.818 pad.11@68.89,52.862 68.89,52.52 68.988,52.422 U18.C3@68.988,52.219 ; U18.C1@69.013,51.194 69.013,51.037 pad.13@69.423,50.627
  Top Layer w0.254: U15.33@65.964,38.773 65.964,39.502 66.022,39.502 66.022,43.098 67.074,44.15 68.814,44.15 69.398,44.734 pad.13@69.423,50.627
  Bottom Layer w0.204: pad.11@68.89,52.862 68.992,52.761 68.992,51.058 pad.13@69.423,50.627
VBAT: C8.2 pad.50@38.258,17.429 SB17.2 U1.6 | length 6.6
  Top Layer w0.204: pad.50@38.258,17.429 38.258,18.725 38.816,19.283 40.036,19.283 40.036,20.045 40.244,20.254 U1.6@40.244,21.516
  Bottom Layer w0.204: SB17.2@37.785,18.191 38.258,17.718 pad.50@38.258,17.429
VDD_MCU: C7.1 C9.1 C10.1 C11.1 C12.1 C13.1 JP5.2 L1.1 pad.51@39.324,17.505 pad.52@42.88,18.877 pad.53@40.264,25.532 pad.64@53.345,24.338 pad.68@52.913,35.336 pad.95@40.925,15.931 pad.97@36.833,15.956 pad.117@49.789,17.302 pad.129@37.064,38.029 pad.130@37.064,37.016 pad.135@35.006,23.271 SB9.1 SB17.1 U1.11 U1.28 U1.50 U1.73 U1.75 U1.100 | length 96.5
  Top Layer w0.204: C12.1@36.462,37.016 pad.130@37.064,37.016 U1.75@37.744,37.016 ; C7.1@36.657,38.029 pad.129@37.064,38.029 38.588,38.029 38.744,37.872 U1.73@38.744,37.016 ; U1.11@42.744,21.516 42.744,20.182 42.906,20.02 C9.1@42.906,19.283 ; U1.28@51.494,24.266 C10.1@52.943,24.266 ; U1.50@51.494,35.266 52.581,35.266 C11.1@52.675,35.36
  Top Layer w0.254: 33.793,23.266 U1.100@35.994,23.266
  POWER+GND w0.5: pad.130@37.064,37.016 pad.129@37.064,38.029 38.258,39.222 48.164,39.222 48.164,39.198 48.692,38.67 52.198,38.67 52.255,38.67 52.198,38.613
  POWER+GND w0.6: pad.135@34.984,23.249 34.984,22.658 35.235,22.408 35.692,22.408 36.149,21.95 36.149,16.64 pad.97@36.833,15.956 ; pad.51@39.324,17.505 40.925,17.505 ; pad.53@40.264,25.532 41.356,24.44 46.69,24.44 48.016,25.766 51.494,25.766 ; pad.95@40.925,15.931 40.925,17.505 ; JP5.2@52.198,41.077 52.198,38.67 52.198,38.613 52.198,37.339 51.494,36.635 51.494,35.336 ; pad.68@52.913,35.336 51.494,35.336 ; pad.64@53.345,24.338 51.494,24.338 ; 40.925,17.505 42.296,18.877 pad.52@42.88,18.877 44.994,18.877 46.086,19.969 46.919,19.969 48.011,18.877 48.011,17.988 48.697,17.302 pad.117@49.789,17.302 51.494,19.007 51.494,24.338 ; 51.494,24.338 51.494,25.766 ; 51.494,25.766 51.494,35.336
  Bottom Layer w0.204: pad.51@39.324,17.505 39.324,18.14
  Bottom Layer w0.6: pad.97@36.833,15.956 pad.95@40.925,15.931
VDDA: C1.1 C5.1 C6.2 L1.2 pad.30@47.744,20.325 pad.31@46.868,26.827 pad.32@40.95,25.659 R2.2 U1.21 U1.22 | length 52.9
  Top Layer w0.204: pad.32@40.95,25.659 40.95,26.421 41.356,26.827 pad.31@46.868,26.827 ; U1.21@47.744,21.516 pad.30@47.744,20.325 ; L1.2@47.96,17.328 48.225,17.592 48.225,19.525 48.225,19.575 47.744,20.056 pad.30@47.744,20.325 ; U1.22@48.244,21.516 48.244,20.558 48.011,20.325 pad.30@47.744,20.325
  Bottom Layer w0.204: C1.1@30.206,51.65 30.275,51.581 30.275,49.897 31.068,49.105 31.068,45.168 33.813,42.423 33.813,35.819 34.27,35.362 34.27,34.418 34.469,34.219 38.435,34.219 39.045,33.609 39.045,29.774 39.68,29.139 40.288,29.139 40.898,28.529 40.898,25.711 pad.32@40.95,25.659 ; pad.31@46.868,26.827 46.868,22.331 47.744,21.456 pad.30@47.744,20.325
VIN: C38.1 CN2.8 pad.48@53.371,0.183 U13.3 | length 5
  Top Layer w1: CN2.8@53.346,-1.439 53.346,0.158 pad.48@53.371,0.183
  Bottom Layer w0.6: C38.1@50.602,1.033 U13.3@52.637,1.033
  Bottom Layer w1: U13.3@52.98,1.376 53.371,0.986 pad.48@53.371,0.183
pads on no net: CN5.7 CN5.8 CN5.9 CN5.11 CN5.12 CN5.13 CN9.11 CN9.12 CN10.9 CN10.10 JP4.7 M1.1 M1.2 M1.3 M2.18 M2.19 M2.23 M2.24 M2.25 M2.26 M2.27 M2.30 M2.31 M2.32 M3.2 M3.3 M3.4 U3.2 U3.3 U3.9 U3.10 U3.11 U4.8 U5.7 U9.3 U9.6 U9.8 U15.4 U15.11 U15.14 U15.16 U15.17 U15.19 U15.21 U15.22 U15.29 U15.40 U15.41 U15.42 U15.43 U15.45 U15.46 U18.A2 U18.B1 U18.B2 U18.C2 U20.A2 U20.B1 U20.B2 U20.C2

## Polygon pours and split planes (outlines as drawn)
GND on GND "Layer GND" (solid, remove dead copper, pour order 22): -5.405,49.23 24.059,49.23 24.059,60.203 81.285,60.203 81.285,37.063 81.285,32.918 81.412,32.918 83.76,32.918 83.779,32.918 cw(c83.779,32.085) 84.613,32.085 84.582,32.054 84.582,24.37 84.582,24.358 83.216,22.992 cw(c82.664,23.544) 82.664,22.763 81.336,22.763 81.311,22.763 81.311,16.185 81.311,-4.567 81.234,-4.567 68.966,-4.567 68.966,14.61 63.683,14.61 63.683,9.276 68.966,9.276 68.966,-4.516 -4.77,-4.516 -4.77,4.729 12.781,4.729 12.781,9.301 15.448,9.301 15.448,18.725 12.68,18.725 12.68,24.186 12.68,24.211 -5.024,24.211 -5.354,24.211 -5.354,49.154
GND on Bottom Layer "Layer GND" (solid, remove dead copper, pour order 20): -5.405,49.23 24.059,49.23 24.059,60.203 81.285,60.203 81.285,37.063 81.285,32.918 81.412,32.918 83.76,32.918 83.779,32.918 cw(c83.779,32.085) 84.613,32.085 84.582,32.054 84.582,24.37 84.582,24.358 83.216,22.992 cw(c82.664,23.544) 82.664,22.763 81.336,22.763 81.311,22.763 81.311,16.185 81.311,-4.567 81.234,-4.567 68.966,-4.567 68.966,14.61 63.683,14.61 63.683,9.276 68.966,9.276 68.966,-4.516 -4.77,-4.516 -4.77,4.729 12.781,4.729 12.781,9.301 15.448,9.301 15.448,18.725 12.68,18.725 12.68,24.186 12.68,24.211 -5.024,24.211 -5.354,24.211 -5.354,49.154
GND on POWER+GND "Power GND" (solid, remove dead copper, pour order 19): -5.405,49.255 24.059,49.255 24.059,60.228 81.285,60.228 81.285,37.089 81.285,32.944 81.412,32.944 83.76,32.944 83.779,32.944 cw(c83.779,32.11) 84.613,32.11 84.582,32.08 84.582,24.396 84.582,24.384 83.216,23.017 cw(c82.664,23.569) 82.664,22.789 81.336,22.789 81.311,22.789 81.311,16.21 81.311,-4.542 81.234,-4.542 68.966,-4.542 68.966,14.635 63.683,14.635 63.683,9.301 68.966,9.301 68.966,-4.491 -4.77,-4.491 -4.77,4.755 12.781,4.755 12.781,9.327 15.448,9.327 15.448,18.75 12.68,18.75 12.68,24.211 12.68,24.236 -5.024,24.236 -5.354,24.236 -5.354,49.179
GND on Top Layer "Top GND" (solid, remove dead copper, pour order 21): -5.388,49.241 24.076,49.241 24.076,60.214 81.302,60.214 81.302,37.075 81.302,32.929 81.429,32.929 83.776,32.929 83.796,32.929 cw(c83.796,32.096) 84.629,32.096 84.599,32.066 84.599,24.382 84.599,24.369 83.232,23.003 cw(c82.68,23.555) 82.68,22.774 81.353,22.774 81.327,22.774 81.327,16.196 81.327,-4.556 81.251,-4.556 68.983,-4.556 68.983,14.621 63.7,14.621 63.7,9.287 68.983,9.287 68.983,-4.505 -4.753,-4.505 -4.753,4.74 12.798,4.74 12.798,9.312 15.465,9.312 15.465,18.736 12.696,18.736 12.696,24.197 12.696,24.222 -5.007,24.222 -5.338,24.222 -5.338,49.165

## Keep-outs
Keep-Out Layer:
  lines w0.1: -3.504,56.086 cw(c-1.088,56.086) -1.088,58.502 7.067,58.502 7.067,58.449 ; -3.5,56.315 -3.5,-1.089 ccw(c-1.085,-1.089) -1.085,-3.504 ; -1.085,-3.5 84.182,-3.5 ; 7.042,49.652 7.042,58.449 ; 7.043,49.652 ccw(c7.343,49.666) 7.356,49.366 ; 7.356,49.358 23.411,49.358 ; 23.36,49.358 ccw(c23.347,49.658) 23.647,49.671 ; 23.652,49.671 23.652,58.499 ; 23.652,58.5 84.181,58.5 ; 84.079,58.501 cw(c84.079,56.085) 86.495,56.085 ; 84.081,-3.501 ccw(c84.081,-1.085) 86.496,-1.085 ; 86.5,-1.085 86.5,56.314

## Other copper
Top Layer:
  text "1" at -2.738,50.017 h1
GND:
  text "2" at -1.238,50.017 h1
POWER+GND:
  text "3" at 0.662,50.017 h1
Bottom Layer:
  text "4" at 2.962,50.017 h1
Multi-Layer:
  pour cut-out: -3.238,51.367 -3.238,49.367 3.512,49.367 3.512,51.367

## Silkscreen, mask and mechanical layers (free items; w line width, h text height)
Top Overlay:
  drawing of 620 lines, arcs and shapes, not listed
  text "USB STLINK" at 58.451,57.434 h0.8
  text "USB" at 25.659,57.129 h0.8
  text "OTG" at 25.659,56.037 h0.8
  text "D7" at 52.863,51.211 h0.7
  text "D6" at 55.352,51.211 h0.7
  text "D5" at 57.841,51.211 h0.7
  text "D15" at 25.659,50.805 h0.7
  text "D14" at 28.225,50.805 h0.7
  text "D13" at 35.845,50.805 h0.7
  text "D12" at 38.842,50.805 h0.7
  text "D11" at 41.026,50.805 h0.7
  text "D10" at 43.49,50.805 h0.7
  text "AVDD" at 30.384,44.861 h0.7
  text "D9" at 46.335,44.175 h0.7
  text "D8" at 48.773,44.175 h0.7
  text "D4" at 60.483,44.175 h0.7
  text "D3" at 63.048,44.175 h0.7
  text "D2" at 65.613,44.175 h0.7
  text "D1" at 68.458,44.175 h0.7
  text "D0" at 70.643,44.175 h0.7
  text "GND" at 36.734,43.464 h0.7
  text "USER" at -0.198,41.508 h1 r90
  text "RESET" at -0.3,29.139 h1 r90
  text "MB1297E" at 0.081,22.306 h1
  text "X" at 66.477,13.848 h0.51
  text "Z" at 68.382,13.848 h0.51
  text "Y" at 68.28,12.603 h0.51
  text "B-L475E-IOT01A1" at 22.967,12.451 h1.52
  text "Y" at 36.048,11.13 h0.51
  text "X" at 37.572,10.114 h0.51
  text "Z" at 35.819,9.123 h0.51
  text "PMOD" at 32.797,6.507 h1 r90
  text "IOREF" at 34.702,4.729 h0.7
  text "A0" at 57.917,3.053 h0.7
  text "A1" at 60.467,3.053 h0.7
  text "A2" at 63.018,3.053 h0.7
  text "A3" at 65.568,3.053 h0.7
  text "A4" at 68.118,3.053 h0.7
  text "A5" at 70.668,3.053 h0.7
  text "NRST" at 39.578,2.875 h0.7
  text "3V3" at 42.418,2.875 h0.7
  text "5V" at 44.851,2.875 h0.7
  text "GND" at 47.488,2.875 h0.7
  text "GND" at 50.125,2.875 h0.7
  text "VIN" at 52.761,2.875 h0.7
Bottom Overlay:
  lines w0.1: 40.518,53.254 43.668,51.476 ; 43.001,53.254 46.151,51.476 ; 45.484,53.254 48.634,51.476 ; 47.967,53.254 51.116,51.476 ; 50.45,53.254 53.599,51.476
  lines w0.254: -1.443,27.386 3.993,27.386 3.993,48.341 -1.443,48.341 -1.443,27.386
  text "ST-LINK DEBUG" at 61.803,54.005 h0.7
  text "5V_ARD" at 54.509,49.365 h0.7 r330
  text "5V_VBAT" at 49.909,49.053 h0.7 r330
  text "5V_USB_FS" at 53.558,48.503 h0.7 r330
  text "5V_ST_LINK" at 58.476,48.485 h0.7 r330
  text "5V_USB_CHARGER" at 51.339,46.563 h0.7 r330
  text "IDD" at 51.948,38.816 h0.7
  text "www.st.com/stm32app-discovery" at 48.443,36.708 h1
  text "TAG connector" at 77.297,26.065 h0.5 r270
  text "SWD Interface" at 78.059,25.557 h0.7 r270
  text "RESET" at 57.206,23.932 h0.7 r270
  text "STLINK" at 58.146,23.906 h0.7 r270
  text "RX" at 66.579,21.798 h0.7
  text "TX" at 69.017,21.773 h0.7
  text "GND" at 25.481,19.715 h0.7
  text "STLINK" at 68.839,17.912 h0.7
  text "UART" at 68.763,16.947 h0.7
  text "GND" at 59.009,16.413 h0.7
Mecha Dim:
  lines w0: 89.79,2.25 90.123,1.25 ; 89.791,21.25 90.124,22.25 ; 89.869,1.25 90.377,1.25 ; 89.87,22.25 90.378,22.25 ; 90.123,8.344 90.123,1.25 ; 90.124,15.155 90.124,22.25 ; 90.456,2.25 90.123,1.25 ; 90.457,21.25 90.124,22.25
  lines w0.1: -12.466,55 93.503,55 ; -9.774,0 93.934,0 ; -5.659,-3.5 0.208,-3.5 ; -3.5,-5.762 -3.5,-1.089 ; -3.5,56.315 -3.5,68.255 ; 0,-6.701 0,64.775 ; 74.224,22.25 90.836,22.25 ; 74.3,1.249 90.988,1.249 ; 77.323,-1.672 77.323,24.694 ; 83,-5.05 83,65.207 ; 83.368,-3.5 96.652,-3.475 ; 84.054,58.5 96.855,58.5 ; 86.5,56.012 86.5,68.001
  lines w0.254: -3.5,66.246 -3.5,66.754 ; -1.976,65.992 -3.5,66.5 ; -1.976,67.008 -3.5,66.5 ; 0,61.546 0,62.054 ; 1.524,61.292 0,61.8 ; 1.524,62.308 0,61.8 ; 36.396,61.8 0,61.8 ; 36.396,66.5 -3.5,66.5 ; 46.604,61.8 83,61.8 ; 46.604,66.5 86.5,66.5 ; 81.476,61.292 83,61.8 ; 81.476,62.308 83,61.8 ; 83,61.546 83,62.054 ; 84.976,65.992 86.5,66.5 ; 84.976,67.008 86.5,66.5 ; 86.5,66.246 86.5,66.754 ; 92.121,1.524 92.629,0 ; 92.121,53.476 92.629,55 ; 92.375,0 92.883,0 ; 92.375,55 92.883,55 ; 92.629,22.396 92.629,0 ; 92.629,32.603 92.629,55 ; 93.137,1.524 92.629,0 ; 93.137,53.476 92.629,55 ; 95.208,-1.976 95.716,-3.5 ; 95.208,56.976 95.716,58.5 ; 95.462,-3.5 95.97,-3.5 ; 95.462,58.5 95.97,58.5 ; 95.716,22.396 95.716,-3.5 ; 95.716,32.603 95.716,58.5 ; 96.224,-1.976 95.716,-3.5 ; 96.224,56.976 95.716,58.5
  text "90 (mm)" at 36.65,65.585 h1.52
  text "83 (mm)" at 36.65,60.885 h1.52
  text "55 (mm)" at 93.543,22.65 h1.52 r90
  text "62 (mm)" at 96.631,22.65 h1.52 r90
  text "MEMS Microphones" at 89.464,8.692 h0.5 r90
  text "21 (mm)" at 90.776,8.598 h1 r90
Mechanical 13:
  circle w0.254: c83,55 r3.25
  circle w0.254: c0,55 r3.25
  circle w0.254: c0,0 r3.25
  circle w0.254: c83,0 r3.25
